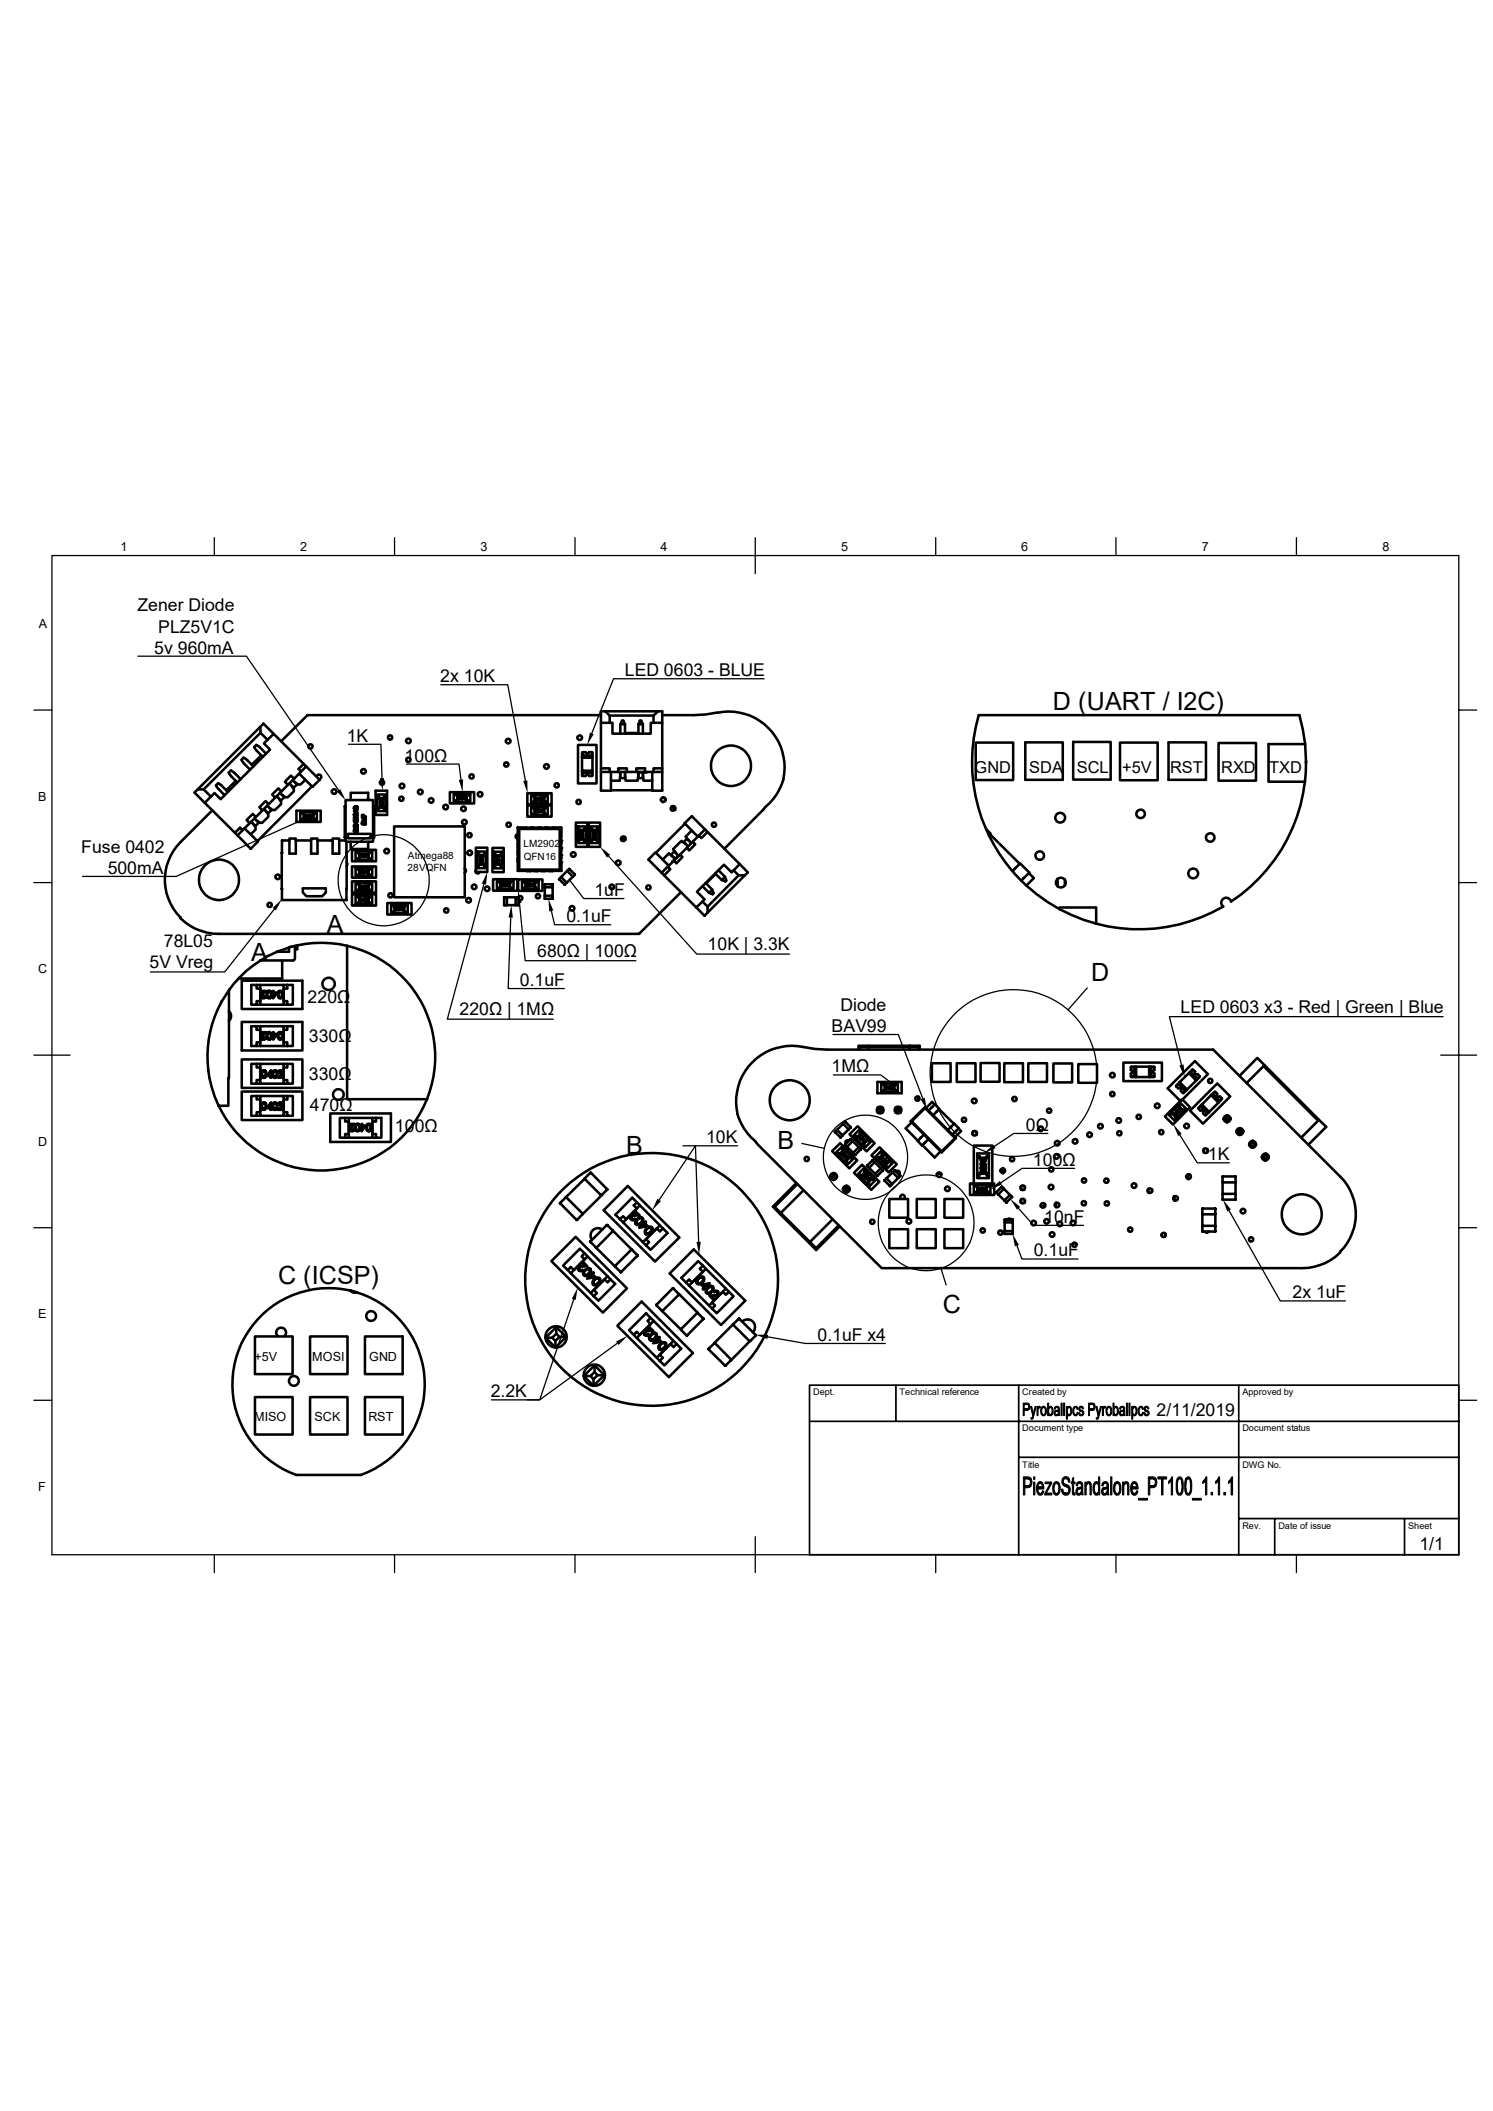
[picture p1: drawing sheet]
<svg xmlns="http://www.w3.org/2000/svg" width="297mm" height="420mm" viewBox="0 0 297 420" stroke-linecap="round" stroke-linejoin="round" font-family="sans-serif">
<defs><g id="words">
<g font-size="5">
<text x="209.5" y="141.2">D (UART / I2C)</text>
<text x="65" y="185.5">A</text>
<text x="50" y="191.2">A</text>
<text x="217.1" y="195.2">D</text>
<text x="124.5" y="229.7">B</text>
<text x="154.6" y="228.6">B</text>
<text x="55.3" y="255.5">C (ICSP)</text>
<text x="187.6" y="261.2">C</text>
</g>
<g font-size="3.5">
<text x="27.3" y="121.6">Zener Diode</text>
<text x="31.5" y="125.9">PLZ5V1C</text>
<text x="30.7" y="130">5v 960mA</text>
<text x="87.6" y="135.8">2x 10K</text>
<text x="124.3" y="134.5">LED 0603 - BLUE</text>
<text x="69" y="147.6">1K</text>
<text x="80.5" y="151.5">100Ω</text>
<text x="16.2" y="169.7">Fuse 0402</text>
<text x="21.4" y="173.9">500mA</text>
<text x="118.2" y="178.3">1uF</text>
<text x="112.7" y="183.5">0.1uF</text>
<text x="32.6" y="188.5">78L05</text>
<text x="106.9" y="190.4">680Ω | 100Ω</text>
<text x="140.8" y="189.1">10K | 3.3K</text>
<text x="29.8" y="192.6">5V Vreg</text>
<text x="103.4" y="196.2">0.1uF</text>
<text x="61.2" y="199.6">220Ω</text>
<text x="91.4" y="202">220Ω | 1MΩ</text>
<text x="167.2" y="201.1">Diode</text>
<text x="234.9" y="201.5">LED 0603 x3 - Red | Green | Blue</text>
<text x="61.4" y="207.4">330Ω</text>
<text x="165.4" y="205.3">BAV99</text>
<text x="61.4" y="214.9">330Ω</text>
<text x="165.4" y="213.4">1MΩ</text>
<text x="61.6" y="221.1">470Ω</text>
<text x="78.6" y="225.2">100Ω</text>
<text x="140.5" y="227.5">10K</text>
<text x="204" y="225">0Ω</text>
<text x="205.5" y="231.9">100Ω</text>
<text x="240.3" y="230.8">1K</text>
<text x="207.7" y="243.3">10nF</text>
<text x="205.7" y="250">0.1uF</text>
<text x="257.1" y="258.3">2x 1uF</text>
<text x="162.6" y="266.8">0.1uF x4</text>
<text x="97.6" y="278">2.2K</text>
<text x="230.1" y="281.7">2/11/2019</text>
<text x="282.4" y="308.4">1/1</text>
</g>
<g font-size="3.3">
<text x="193.9" y="153.8">GND</text>
<text x="204.8" y="153.8">SDA</text>
<text x="214.2" y="153.8">SCL</text>
<text x="223.3" y="153.8">+5V</text>
<text x="232.8" y="153.8">RST</text>
<text x="242.9" y="153.8">RXD</text>
<text x="252.5" y="153.8">TXD</text>
</g>
<g font-size="2.5">
<text x="24" y="109.6">1</text>
<text x="59.7" y="109.6">2</text>
<text x="95.6" y="109.6">3</text>
<text x="131.4" y="109.6">4</text>
<text x="167.3" y="109.6">5</text>
<text x="203.2" y="109.6">6</text>
<text x="239.1" y="109.6">7</text>
<text x="275" y="109.6">8</text>
<text x="7.7" y="125">A</text>
<text x="7.6" y="159.3">B</text>
<text x="7.6" y="193.7">C</text>
<text x="7.6" y="228">D</text>
<text x="7.6" y="262.3">E</text>
<text x="50.6" y="270.8">+5V</text>
<text x="62.1" y="270.8">MOSI</text>
<text x="73.5" y="270.8">GND</text>
<text x="50.5" y="282.7">MISO</text>
<text x="62.6" y="282.7">SCK</text>
<text x="73.3" y="282.7">RST</text>
<text x="7.6" y="296.6">F</text>
</g>
<g font-size="2">
<text x="81.1" y="173.2">28VQFN</text>
<text x="81.2" y="170.8">Atmega88</text>
<text x="104.1" y="168.6">LM2902</text>
<text x="104.2" y="171">QFN16</text>
</g>
<g font-size="1.8">
<text x="161.8" y="277.6">Dept.</text>
<text x="178.9" y="277.6">Technical reference</text>
<text x="203.4" y="277.6">Created by</text>
<text x="247.1" y="277.6">Approved by</text>
<text x="203.4" y="284.8">Document type</text>
<text x="247.1" y="284.8">Document status</text>
<text x="203.4" y="292">Title</text>
<text x="247.1" y="292">DWG No.</text>
<text x="247.1" y="304.2">Rev.</text>
<text x="254.3" y="304.2">Date of issue</text>
<text x="280.1" y="304.2">Sheet</text>
</g>
</g></defs>
<g fill="none" stroke="#000" stroke-width=".51">
<path d="M40.7 159.7l2-1.9 1.2 1.2 9.8-9.9-1.2-1.2 1.9-1.9 6 6-1 1 .5 .5-1.4 1.4-.6-.6-1.2 1.2 .6 .7-1.3 1.3-.6-.7-1.3 1.3 .6 .6-1.3 1.3-.6-.6-1.2 1.2 .6 .6-1.3 1.4-.6-.7-1.2 1.3 .6 .6-1.4 1.4-.5-.5-1.1 1M42 158.5l-1.5-1.4h-1.2l-.6 .6 8.5 8.5M45.3 157.6l-1.4-1.4-.5-.4-.4 .5 .1 .2 1.6 1.7M46.9 155.4l-1.9 1.8M47.9 155l-1.4-1.4-.6-.3-.4 .4 .1 .3 1.6 1.7M50.4 152.5l-1.4-1.4-.6-.4-.4 .5 .2 .3 1.5 1.6M51.8 145.8l-11.3 11.3M51.8 144.6l-12.5 12.5M52 150.3l-1.9 1.8M52.9 149.9l-1.3-1.4-.6-.3-.4 .4v.2l1.7 1.8M54.4 146l-2-2-.6 .6v1.2l1.4 1.4M55.3 158.7l.6 .9v.4l-1.2 1.2h-.4l-.8-.6"/>
<path d="M55.7 157.7l.9 .9-.7 .7-.9-.9M56 157.5l-1.3 1.2M57.9 156.2l.6 .8v.4l-1.3 1.2h-.4l-.8-.5M58.2 155.2l.9 .9-.7 .6-.8-.8M58.5 154.9l-1.2 1.3M60.4 152l.5 .5-1 1M60.7 155.2l-.9 .9h-.4l-.9-.6M60.9 152.5l2.7 2.7-1.5 1.3-2.6-2.6M62.1 156.5l-10.9 10.8M63 154.5a.46 .46 0 0 1 .5-.4 .46 .46 0 0 1 .4 .4 .46 .46 0 0 1-.4 .5M68.7 159.3v8M68.8 159.3l.1-.1h5.2l.1 .1v8l-.1 .2h-5.2"/>
<path d="M69.8 159.2v-1.5h3.4v1.5M74.7 157.3h2.3v4.8h-2.3zM75.1 158.8h1.6v1.9h-1.6zM75.1 158.1h1.6v.4h-.3v.3h-1v-.3h-.3zM75.1 158.5v.3M75.6 159.8l.4-.1 .2 .2h-.2v.2zM75.6 159.4l.4-.1 .2 .3-.5 .1zM75.6 158.9h.3l.2 .2 .1-.3v.5l-.4-.4-.2 .1 .2 .2h-.2zM75.6 159.4l.4-.1 .1 .3h-.4zM75.7 159.9h.3v.1zM75.8 159.2h.1M76.7 158.5v.3"/>
<path d="M89.5 157.6h4.8v2.3h-4.8zM90.3 157.9h.4v.3h.3v1h-.3v.3h-.4zM90.7 157.9h.3M90.7 159.5h.3M91 157.9h1.8v1.6h-1.8zM91.1 158.4h.3l-.2 .2 .1-.1zM91.1 158.8l.1-.1-.1 .2h.3l-.3 .1zM91.5 158.5h.4l-.1 .5-.3-.1zM92 158.4v.1h.3l-.3 .5zM92 158.6h.2l-.2 .3zM92.5 158.5l.2 .1-.1 .4-.2-.2zM92.5 158.4l.2 .1a.3 .3 0 0 1 .1 .3 .3 .3 0 0 1-.3 .2l-.1-.2z"/>
<path d="M92.8 157.9h.8v1.6h-.5M92.8 159.5h.3M93.1 157.9v.3h-.3v1h.3v.3M104.9 157.8h4.8v2.3h-4.8zM106.1 158.2v.3h.3v.9h-.3v.3M106.1 158.2h-.4v1.5h.7M106.1 158.2h.3M106.4 158.2h1.8v1.5h-1.8zM106.5 158.8l.3-.1v.6l-.3-.2zM106.6 158.8h.2l-.1 .4h-.1zM107.2 158.8v.2h-.2zM107.2 158.7l.1 .4-.1 .2v-.2h-.3z"/>
<path d="M107.4 158.7l.3 .1v.5l-.3-.2zM107.4 158.8h.3l-.1 .4-.2-.1zM107.8 158.8l.4-.1v.3l-.3 .2 .3 .1h-.4l.3-.4v-.1l-.2-.1v.2zM108.2 158.5h.3v-.3h.5v1.5h-.5v-.3h-.3zM108.2 159.7h.3M108.2 158.2h.3M115 148.2h3.7v7.7h-3.7zM115.8 150.7h2.1v2.6h-2.1zM115.8 153.3v.2h2.1M115.8 150.7v-.1h2.1v.1M115.8 153.5v.8h.1M115.9 154.4v-.6h1.9v.6h-.6l-.3-.3-.3 .1-.1 .2"/>
<path d="M115.9 149.7h-.1v.9M115.9 154.4h.6M116.5 149.6h-.6v.7h1.9v-.7h-.6l-.3 .4-.3-.1-.1-.3M117.8 149.7l.1 .9M117.9 153.5l-.1 .8M117.9 153.3v.2M119.5 152.9h1.8v.7M119.5 143.8h2.3v2.2h7.7v-2.2h2.2v9.1h-1.7v.7M119.5 153.6h12.2M119.5 142.3h-58.3l-5.3 5.2M120.4 141.5l.9 .9v1.4M121.3 142.4h8.7"/>
<path d="M121.5 157.2h8.3M123 153.6v-.7h1.7v.7M123.4 144.1v1.9M123.4 153.6v1.2h.9v-1.2M123.4 153.9l-.1 1.4h-1.8M123.7 143.4h.3l.3 .7h-.9zM124.3 154.1l.2 1.2h2.3l.2-1.2M124.3 144.1v1.9M124.3 145.8h2.7M126.6 153.6v-.7h1.7v.7M127 144.1v1.9M127 153.6v1.2h.9v-1.1"/>
<path d="M127 144.1l.3-.7h.3l.3 .7M127 144.1h.9M127.1 153.6l1 .1M127.9 153.9l.1 1.4h1.8M127.9 144.1v1.9M128.1 153.6h.5M130 142.4l.9-.9h.8v2.3M130 142.4v1.4M130.9 141.5h-11.4v15.8h2v-3.7M131.4 159.1l.5 .5M131.7 152.9v4.4h-1.9v-3.7M131.9 158.6l.6 .5"/>
<path d="M142.6 141.8a11.1 11.1 0 0 1 13.2 13.2M142.6 141.8l-2.3 .4-2.3 .1h-6.3M155.9 155a11.1 11.1 0 0 1-3.7 5.6l-8.1 8.3M194.1 147.7h7.4v7.5h-7.4zM204 147.7h7.4v7.5h-7.4zM213.5 147.6h7.4v7.5h-7.4zM222.8 147.7h7.5v7.5h-7.5zM232.5 147.7h7.4v7.5h-7.4zM242.4 147.8h7.5v7.5h-7.5zM259.6 155.5a33.1 33.1 0 0 1-14.7 23.9 .98 .98 0 0 0-1.5-.6 .98 .98 0 0 0-.1 1.5M259.6 148a37 37 0 0 1 0 7.5M259.6 148h-7.3v7.5h7.3"/>
<path d="M259.6 148l-.4-2.9-.7-2.8h-63.8a33.1 33.1 0 0 0 1.5 22.7l.9 .9-.4 .3a33.6 33.6 0 0 0 4.7 7.1M42.2 161.2l-6.3 6.4a10.7 10.7 0 0 0-2.2 11.6 10.7 10.7 0 0 0 9.9 6.6h83.5l8.4-8.3M48.3 165.2l-1.1 1M48.6 164.8l2.7 2.6-1.4 1.5-2.7-2.7M50.2 163.8l.6 .8v.5l-.9 .9M50.6 162.8l.9 .9-.7 .6-.8-.8M50.9 162.6l-1.2 1.2M52.8 161.2l.6 .9v.4l-1.2 1.2h-.5l-.8-.5M53.1 160.3l.9 .9-.7 .6-.8-.8M53.4 160l-1.2 1.2M56 169.7l.1 7.2M56.1 176.9h.1"/>
<path d="M56.1 176.8v2.3h12.8l.1-2.3M56.1 169.7h.1M57.6 166.8h1.2v3h-1.2zM57.6 167.2h-1.5v2.5M58.8 167.2h3.1M59 161.3h4.8v2.2h-4.8zM60.2 161.6v.3h.3v1h-.3v.3M60.2 161.6h-.5v1.6h.8M60.2 161.6h.3M60.2 176.7h4.6v.9l-.7 .7h-3.1l-.8-.7zM60.5 161.6h1.8v1.6h-1.8zM60.6 162.2a.22 .22 0 0 1 .2 0 .22 .22 0 0 1 .1 .2v.3h-.3z"/>
<path d="M60.6 162.2l.3 .1-.1 .4-.2-.1zM61.3 162.3v.2h-.2zM61.3 162.1l.1 .5-.1 .1v-.1h-.3zM61.5 162.2l.2-.1 .1 .2-.1 .4-.3-.1zM61.5 162.2l.3 .1-.1 .4-.2-.1zM61.9 166.8h1.3v3h-1.3zM61.9 162.2h.3l-.2 .4 .2 .1h-.4l.4-.3-.1-.2-.2 .1zM62.3 161.9h.3v-.3h.4v1.6h-.4v-.3h-.3zM62.3 163.2h.3M62.3 161.6h.3M63.2 167.2h3M66.2 166.8h1.3v3h-1.3z"/>
<path d="M66.2 167.1l-.4 .2M67.5 167.2h1.2M68.7 160.4h-.1v6.2h.1M68.8 167.3l.1 .2M68.9 169.7h.1M68.9 167.5v2.3M69 171.5l.1 .3-.1 .5M69 169.7v7.1M69.2 165.9h4.5v.9h-4.5zM69.8 167.5v1.4h3.4v-1.4M70 177.9h4.8v2.3h-4.8zM70 175.3h4.8v2.3h-4.8z"/>
<path d="M70 172.4h4.8v2.2h-4.8zM70 169.1h4.8v2.3h-4.8zM70.4 161.4l.8-.4-.3 .2v.3l.3 .3zM70.4 162.6l.8 .1h-.7v.1zM70.4 164.2l.2-.2h.4l.2 .2-.1 .4-.2 .2-.4-.1zM70.4 160.6l.6-.2 .2 .5h-.8zM70.4 163.1l.2-.1 .3 .2-.4-.1v.3h.2l-.1 .1-.2-.1zM70.5 160.6h.2v.2h-.2zM70.5 161.9l.2-.1 .5 .4-.4-.2v.2a.23 .23 0 0 1-.3 .1 .23 .23 0 0 1 0-.4zM70.5 165l.1-.1a.36 .36 0 0 1 .4 0 .36 .36 0 0 1 .2 .4v.2h-.8zM70.5 161.4l.3-.2v.3zM70.5 165.1l.2-.2 .3 .1 .1 .4h-.6z"/>
<path d="M70.7 172.7h.5v.3h.3v1h-.3v.3h-.5zM70.7 169.4h.5v.3h.3v1h-.3v.3h-.5zM70.8 163.6l.1 .3zM70.8 160.6h.3v.2h-.3zM70.9 163.2l.2 .2 .1-.4v.5zM71.2 178.3v.3h.3v.9h-.3v.3M71.2 178.3h-.5v1.5h.8M71.2 175.7v.3h.3v1h-.3v.3M71.2 175.7h-.5v1.6h.8M71.2 169.4h2.8v1.6h-.4M71.2 172.7h.3M71.2 178.3h.3"/>
<path d="M71.2 175.7h.3M71.2 174.3h.3M71.2 171h.3M71.5 178.3h1.8v1.5h-1.8zM71.5 175.7h1.8v1.6h-1.8zM71.5 172.7h1.8v1.6h-1.8zM71.5 169.4v1.6h1.8M71.5 173.2h.4l-.3 .4 .1 .1 .2-.1-.1 .2-.3-.1 .3-.4zM71.5 169.9h.4l-.3 .4 .1 .1 .2-.1-.1 .2-.3-.1 .3-.4zM71.6 176.3h.3l-.1 .5-.2-.1zM71.6 178.9h.3v.4l-.3-.1zM71.6 176.4h.3l-.1 .4-.2-.1z"/>
<path d="M72 162.1l.1 .3h.2l.1-.3v.3l.4 .1h-.8zM72 162.8l.8-.2-.6 .2 .6 .3-.6 .3 .6 .1-.8-.1 .6-.3zM72 173.3h.3v.5l-.3-.1zM72 163.7h.2l-.1 .2 .1 .1 .4-.4 .2 .4-.2 .1 .1-.4h-.2l-.2 .3h-.2zM72.1 173.3h.2l-.1 .4h-.1zM72.1 169.9l.2 .1v.5l-.3-.1zM72.1 170h.2l-.1 .4-.1-.1zM72.3 178.9v.3h-.2zM72.3 176.4v.2h-.2zM72.3 178.8l.1 .4-.1 .2v-.2h-.3zM72.3 176.2l.1 .5-.1 .1v-.1h-.3zM72.5 178.9l.2-.1a.26 .26 0 0 1 .2 .3 .26 .26 0 0 1-.3 .2 .26 .26 0 0 1-.2-.3z"/>
<path d="M72.5 176.3a.28 .28 0 0 1 .3 .2 .28 .28 0 0 1-.1 .3l-.2-.1zM72.5 173.2l.3 .1-.3 .5zM72.5 169.9l.3 .2-.3 .4zM72.6 178.9h.2l-.1 .4-.2-.1zM72.6 173.4h.1l-.1 .3zM72.6 170.1h.1l-.1 .2zM72.6 176.3l.2 .1-.2 .4-.1-.1zM72.9 173.3h.3v.5l-.3-.1zM72.9 170l.3-.1v.6a.34 .34 0 0 1-.3-.5zM72.9 178.9l.3-.1 .1 .2-.3 .3 .3 .1h-.4l.3-.4-.1-.2-.1 .2zM72.9 173.3h.3l-.1 .4h-.2zM72.9 170l.3 .1-.1 .3h-.2z"/>
<path d="M72.9 176.3h.4l-.3 .4 .3 .1h-.4l.3-.4v-.1l-.3 .1zM73.3 176h.3v-.3h.4v1.6h-.4v-.3h-.3zM73.3 172.7h.7v1.6h-.4M73.3 169.4v1.6M73.3 179.8h.3M73.3 177.3h.3M73.3 178.3h.3M73.3 175.7h.3M73.3 174.3h.3M73.3 171h.3M73.6 178.3h.4v1.5h-.4v-.3h-.3v-.9h.3zM73.6 172.7v.3h-.3v1h.3v.3"/>
<path d="M73.6 169.4v.3h-.3v1h.3v.3M74.2 160.4h.2v6.2h-.2M75.1 161h.3v-.3h1v.3h.3M75.1 160.7v.3M75.6 160.3l.5-.1 .1 .2-.5 .2zM75.6 160.3l.4-.1 .1 .2-.3 .1zM76.7 160.7v.7h-1.6v-.4M77 179.7h4.9v2.2h-4.9zM78.4 164.4h14.1v14.1h-14.1zM92.4 172.8l.3 .4-.3 .5M94.7 168.7h2.2v4.8h-2.2zM94.7 173a.46 .46 0 0 0 .1 .7 .46 .46 0 0 0 .7-.2"/>
<path d="M95 172v-1.9h1.6v1.9M95 169.8h.3v.3h1v-.3h.3M95 172h1.6M95 172v.3M95.3 172h1v.3h.3v.4h-1.6v-.4h.3zM95.5 171.2l.4-.1 .2 .3-.5 .1zM95.5 170.3l.4-.1 .2 .1v.2l-.5 .1zM95.5 171.6l.3 .3 .2-.1v-.2l.1 .3-.2 .1-.4-.3v.3zM95.5 171.2h.4l.1 .2-.4 .1zM95.5 170.3h.5v.2l-.4 .1zM95.6 170.7l.5 .3h-.6l.1-.1zM95.7 170.8l.2 .1h-.2z"/>
<path d="M96.6 169.8v-.4h-1.6v.7M96.6 169.8v.3M96.6 172v.3M98 168.7h2.2v4.8h-2.2zM98.1 174.9h4.8v2.3h-4.8zM98.3 170.2h1.6v1.8h-1.6M98.3 169.9h.3v.3h1v-.3h.3M98.6 172h1v.3h.3v.5h-1.6v-.5h.3zM98.8 171.2h.4l.2 .2-.5 .1zM98.8 170.3h.4l.2 .2-.6 .1zM98.8 171.6l.5 .3-.2-.2a.16 .16 0 0 1 .2 .2 .16 .16 0 0 1-.3 0l-.2-.2v.3zM98.8 170.4v-.1a.21 .21 0 0 1 .3 0 .21 .21 0 0 1 .1 .3h-.3z"/>
<path d="M98.8 171.2h.4l.1 .3h-.4zM98.8 175.3h.5v.3h.3v1h-.3v.2h-.5zM98.9 170.7l.5 .3-.5 .1-.1-.1h.1zM98.9 170.8l.3 .2h-.3zM99.3 176.8h.3M99.3 175.3h.3M99.6 175.3h1.8v1.5M99.6 175.3v1.5h1.8M99.6 175.7h.4l-.3 .4v.2l.3-.2-.1 .2h-.2l-.1-.2 .3-.3zM99.9 170.2v-.7h-1.6v2.8M99.9 172v.3M100.1 175.8a.26 .26 0 0 1 .3 .2 .26 .26 0 0 1-.3 .3z"/>
<path d="M100.1 175.9l.1-.1a.2 .2 0 0 1 .2 .2 .2 .2 0 0 1-.3 .2zM100.3 178.5h.5M100.3 178.5v1.6M100.3 178.5v.1M100.6 175.7v.2h.3l-.3 .4zM100.6 175.9h.2l-.2 .3zM100.8 178.5h1.8v1.6h-1.8zM101 175.9h.3l-.1 .4-.2-.1zM101 175.8a.26 .26 0 0 1 .4 .3 .26 .26 0 0 1-.4 .2zM101.4 175.3h.8v1.5h-.5M101.4 176.8h.3M101.7 175.3v.3h-.3v1h.3v.2"/>
<path d="M102.6 178.5h.6M102.6 178.5v.1M103 164.7h8.6l-.3 .2h-8zM103 165.9a.47 .47 0 0 0-.4 .5 .47 .47 0 0 0 .4 .5M103 170.7v.9M103 166.4v.9M103 167.8v.9M103 169.2v.9M103.1 175h4.8v2.3h-4.8zM103.1 178.5v.1M103.1 178.5a.43 .43 0 0 1 .7-.2 .43 .43 0 0 1 0 .7 .43 .43 0 0 1-.6-.1M103.2 178.5v1.6l-.6-.1"/>
<path d="M103.3 164.9v8.1M103.8 175.3h.5v.3h.3v1h-.3v.3h-.5zM104.3 175.3h.3M104.3 176.9h.3M104.6 175.3h1.8v1.6h-1.8zM104.6 175.8h.4l-.3 .3v.2l.3-.1-.1 .2-.3-.1v-.2l.3-.2zM104.7 173.3h.9M104.8 164.7h-1.8v8.6h8.6M104.9 160.2h4.8v2.3h-4.8zM105.1 175.9l.1-.1a.34 .34 0 0 1 .2 .5h-.3zM105.2 175.9l.1-.1 .1 .1-.1 .4-.2-.1zM105.6 175.8v.1h.3l-.3 .5z"/>
<path d="M105.6 164.7h.6M105.6 176h.2l-.2 .2zM106 175.9l.1-.1a.37 .37 0 0 1 .2 .6l-.3-.2zM106 175.9h.3l-.1 .4-.2-.1zM106.1 160.6v.2h.3v1h-.3v.3M106.1 162.1h.3M106.2 173.3h.8M106.4 160.6h1.8v1.5h-1.8zM106.4 160.6h-.7v1.5h.4M106.4 161h.4l-.3 .3v.2l.3-.1a.17 .17 0 0 1-.2 .2 .17 .17 0 0 1-.2-.2 .17 .17 0 0 1 .2-.2l.1-.1zM106.4 175.3h.7v1.6h-.7M106.7 175.3v.3h-.3v1h.3v.3"/>
<path d="M106.9 161.1l.3-.1 .1 .5-.2 .1-.2-.1zM106.9 161.2l.3-.1-.1 .4h-.1zM107 164.7h.7M107.4 161v.2h.3l-.3 .4zM107.4 161.2h.2l-.2 .3zM107.6 173.3h.9M107.8 161.1l.3-.1 .1 .2a.25 .25 0 0 1 0 .3 .25 .25 0 0 1-.4 .1 .25 .25 0 0 1 0-.4zM107.8 161.2h.3l-.1 .3h-.2zM108.2 160.6h.8v1.5h-.5M108.2 162.1h.3M108.4 176.5h1.5v1.7h-1.5zM108.4 176.5v-.6h1.5v.6"/>
<path d="M108.4 178.2v.6h1.5v-.6M108.4 178.8h.1M108.4 176.5h.1M108.4 178.2v.1M108.4 175.9v.1M108.5 164.7h.6M108.5 160.6v.2h-.3v1h.3v.3M109.1 173.3h.8M109.9 164.7h1.7M109.9 178.2v.1M109.9 175.9v.1M109.9 178.8h.1"/>
<path d="M109.9 176.5h.1M111.3 175l1 1M111.3 174.9v.1M111.3 173h-8l-.3 .3M111.6 174.5h.1M111.6 164.7v8.6l-.3-.3v-8.1M111.6 170.1l.1 .6M111.6 168.7l.1 .5M111.6 167.3l.1 .5M111.6 164.7l.1 1.7M111.6 173.3h.1M111.6 171.6v1.7"/>
<path d="M111.6 174.5l-.3 .5M112.3 176h.1M112.4 176h.1M112.7 175.6l-.3 .4M112.7 175.6v.1M112.8 173.3l1.2 1.1-1.3 1.2-1.1-1.1zM112.8 173.3h.1M112.9 173.3l.3-.4 1.1 1-.3 .5M112.9 173.2v.1M113.2 172.9h.1M113.9 174.4h.1M114.6 163.7h2.2v4.8h-2.2z"/>
<path d="M114.9 165.1h1.6v1.9h-1.6zM114.9 164.8h.3v.3h1v-.3h.3M114.9 167v.3M115.2 167h1v.3h.3v.4h-1.6v-.4h.3zM115.4 166.2l.5-.1 .1 .2-.4 .2-.2-.1zM115.4 166.5l.3 .4 .2-.1-.1-.2h.1l.1 .3h-.3l-.3-.2v.2zM115.4 165.3l.5-.1 .1 .2a.33 .33 0 0 1-.3 .2 .33 .33 0 0 1-.3-.2zM115.4 166.2h.4l.1 .2h-.4zM115.4 165.4l.4-.1 .1 .2-.3 .1zM115.5 165.7l.5 .3h-.6l.1-.1zM115.6 165.8l.2 .1h-.2zM115.8 166.6h.1"/>
<path d="M116.5 164.8v-.4h-1.6v.7M116.5 164.8v.3M116.5 167v.3M117.1 163.7h2.3v4.8h-2.3zM117.5 165.1h1.5v1.9h-1.5zM117.5 164.4h1.5v.4h-.3v.3h-.9v-.3h-.3zM117.5 167.3h.3v-.3h.9v.3h.3M117.5 164.8v.3M117.5 167v.3M118 166.2l.4-.1 .2 .1h-.2v.3zM118 165.3l.2-.1 .3 .2 .1-.2v.4l-.5-.3v.3zM118 165.7h.5a.29 .29 0 0 1-.2 .4 .29 .29 0 0 1-.3-.4z"/>
<path d="M118 166.6l.5-.1a.27 .27 0 0 1-.2 .4 .27 .27 0 0 1-.3-.3zM118.1 166.6h.3l.1 .2h-.4zM118.1 166.2h.3v.2zM118.1 165.7h.4a.21 .21 0 0 1-.2 .3 .21 .21 0 0 1-.2-.3zM119 167v.7h-1.5v-.4M119 164.8v.3M124.3 166.5l-.7 .7M132.8 172.4l-1.2 1.3M133.1 172.3l-2.7-2.7-1.4 1.4 3.1 3.2M133.5 161.1l.1 .1M133.6 160.4l.7 .7M134.1 171.2l-1.3 1.2"/>
<path d="M134.1 170.7l-1-.9-1.3 1.2M134.2 171.1l-.3 .3M134.9 170.3l-.7 .7M135 170.3l-.9-.9-.6 .7 .8 .8M135.3 170l.5 .5-1.2 1.2-.5-.5M136.3 163.9l-5.8 5.8M136.5 168l-.9-.7-1.7 1.7 .7 .9M137.5 167.7l-.8-.8-.7 .6 .9 .9M137.6 165.2l-1.2 1.3 .9 1M137.8 167.5l.5 .5-1.2 1.2-.5-.5M138.8 166.5l-2.6-2.7 1.4-1.4 9.6 9.5M139.7 176.3l1.4 1.3"/>
<path d="M139.7 179.4l1.1 1M140.3 165l-6.2 6.2M140.4 175.7l1.3 1.3M140.8 165.5l-1.3 1.3-.5-.6M141.1 177.6l.6-.6 .2 .7-.1 .2zM142.2 173.8l1.4 1.3M142.4 173.9l-1.9 1.9M142.9 173.1l1.3 1.4M143.6 175.1l.6-.6 .3 .7-.2 .2zM145.9 173.1l1 1.1h1.3M146.9 174.2l-6.1 6.2M147.2 171.9l-1.7 1.7-1.5-1.6-5.4 5.4 1.6 1.5-1.7 1.7-6.4-6.4 1.2-1.3-.5-.5"/>
<path d="M147.2 171.9l1.6 1.7-8 8M196.2 165l.6 1.2M196.9 166l6 5.9M201.4 173.3l1.5-1.5 1.9 1.8-1.6 1.6M201.4 173.3l1.8 1.9M203.2 175.2l1 1M204.2 176.2l2 1.7 2.2 1.6 2.4 1.4M204.7 173.7l1 1-1.5 1.5M210.4 174.8v1.6M211.8 175v1.2M44 199.4a22.4 22.4 0 0 0-2.6 13.6M44 199.3l-.1 .1"/>
<path d="M45.6 196.9v17.6M48.1 195.1h12.1v5.6h-12.1zM50 196h1.1v.7h.7v2.5h-.7v.7h-1.1zM51.1 196h.7M51.1 199.9h.7M51.8 196h4.6v3.9h-4.6zM51.9 197.1h1l-.5 .6a.41 .41 0 0 0-.3 .4 .41 .41 0 0 0 .1 .4h.3l.4-.3-.3 .4h-.3a.52 .52 0 0 1-.3-.4 .52 .52 0 0 1 .2-.5l.4-.4h-.7zM52.7 190.5a22.7 22.7 0 0 0-8.6 8.8M53.2 197.2l.4-.1 .4 .3v.8l-.3 .4-.4-.1-.2-.2-.1-.7zM53.3 197.4a.34 .34 0 0 1 .4-.1 .34 .34 0 0 1 .2 .3l-.1 .7-.4 .2-.2-.4zM53.4 190.2l-.7 .3M54.3 197.1h.1v.4h.7l-.7 1.1-.1-1h-.2v-.1h.2z"/>
<path d="M54.4 197.6h.5l-.5 .6zM55.1 189.4l-1.7 .8M55.4 197.3l.4-.2 .4 .4a1.06 1.06 0 0 1-.2 1.1h-.4l-.3-.2-.1-.7zM55.5 197.4l.4-.1 .1 .1 .1 .8-.2 .3h-.3l-.2-.3zM56.1 191.1v3.6h-8.6v-.1M56.4 196h1.9v3.9h-1.2M56.4 199.9h.7M57.1 196v.7h-.7v2.5h.7v.7M57.5 188.5v.9h-2.4M57.7 188.4l-2.6 1M58 188.3l-.3 .1M58.6 190.8l-.1 .2-.2 .1h-6.6"/>
<path d="M58.7 188.2v2.6M59.1 188.1v.8h-.4M59.1 188.1a22.6 22.6 0 0 1 9.9 .1M59.1 188.1l-1 .2M69 188.2a22.7 22.7 0 0 1 16 30.5M69 188.2v30.5h16M77.8 180h.4v.3h.3v1h-.3v.3h-.4zM78.2 180h.3M78.2 181.6h.3M78.5 180h1.9v1.6h-1.9zM78.6 180.5h.4l-.3 .3v.2l.3-.1-.1 .2-.3-.2 .3-.3zM79 180.6l.2-.1 .2 .1-.1 .5-.2-.1z"/>
<path d="M79.5 180.5l.1 .1h.2l-.3 .5zM79.6 180.7h.2l-.2 .2zM79.9 180.6l.2-.1a.28 .28 0 0 1 .2 .3 .28 .28 0 0 1-.3 .2zM80 180.6a.2 .2 0 0 1 .3 .2 .2 .2 0 0 1-.3 .1zM80.4 180h.7v1.6h-.4M80.4 181.6h.3M80.7 180v.3h-.3v1h.3v.3M100.3 180.1h.5M100.3 180v.1M100.8 180v.1M103.1 180v.1M140.8 180.4v1.2l-.6 .6-1.7-1.6"/>
<path d="M210.8 180.9l4.8 2.1 2.5 .8M210.8 180.9v-.3h7.3v3.2M243.3 180.4a33.4 33.4 0 0 1-25.2 3.4M41.4 213v.1M41.4 213a22.7 22.7 0 0 0 19.6 19.7 22.7 22.7 0 0 0 24-14M45.4 214.4v5.6h-2M45.4 214.6h.1M45.5 201.2a1.25 1.25 0 0 1 0 1.9M45.5 214.5h.1M48.1 217.2h12.1v5.6h-12.1zM48.1 210.8h12.1v5.7h-12.1zM48.1 203.3h12.1v5.7h-12.1z"/>
<path d="M50 204.2h1.1v.7h.7v2.5h-.7v.7h-1.1zM51.1 218.1v.6h.7v2.6h-.7v.7M51.1 218.1h-1.1v3.9h1.8M51.1 211.7v.7h.7v2.5h-.7v.7M51.1 211.7h-1.1v3.9h1.8M51.1 204.2h.7M51.1 218.1h.7M51.1 211.7h.7M51.1 208.1h.7M51.8 218.1h4.6v3.9h-4.6zM51.8 211.7h4.6v3.9h-4.6zM51.8 204.2h4.6v3.9h-4.6z"/>
<path d="M51.9 205.4h1l-.8 .8a.33 .33 0 0 0 .3 .5 .33 .33 0 0 0 .3-.3h.2l-.1 .2-.2 .2h-.4a.5 .5 0 0 1-.2-.4 .5 .5 0 0 1 .2-.5l.4-.4h-.7zM52.1 219.5l.5-.2 .4 .5-.1 .8-.2 .2h-.4a1.13 1.13 0 0 1-.2-1.3zM52.1 213.1l.2-.1a.47 .47 0 0 1 .6 .4l.1 .6a.49 .49 0 0 1-.6 .5 .49 .49 0 0 1-.4-.6zM52.2 219.6l.3-.1 .2 .1 .1 .7a.33 .33 0 0 1-.2 .4 .33 .33 0 0 1-.4-.2zM52.2 213.2l.3-.1 .3 .2v.7a.37 .37 0 0 1-.2 .3 .37 .37 0 0 1-.4-.1zM53.2 205.4l.4-.1a.83 .83 0 0 1 .4 1.2l-.3 .3-.5-.1-.2-.9zM53.3 205.6a.35 .35 0 0 1 .4-.1 .35 .35 0 0 1 .2 .3v.5a.36 .36 0 0 1-.4 .4 .36 .36 0 0 1-.3-.4zM53.8 219.7v.6h-.5zM53.8 213.3v.6h-.5zM53.9 219.3v1h.2v.2h-.2v.3h-.1v-.3h-.7zM53.9 212.9v1h.2v.2h-.2v.3h-.1v-.3h-.7zM54.3 213.2l.3-.3 .3 .1 .3 .4v.6a.47 .47 0 0 1-.5 .5 .47 .47 0 0 1-.5-.4z"/>
<path d="M54.3 205.4h.1v.3h.7l-.7 1.1-.1-.9h-.2v-.2h.2zM54.4 219.4l.4-.1 .4 .5v.6l-.3 .4h-.4l-.3-.3v-.8zM54.4 219.6a.34 .34 0 0 1 .4-.1 .34 .34 0 0 1 .2 .3v.6a.34 .34 0 0 1-.3 .3 .34 .34 0 0 1-.3-.4zM54.4 205.9h.5l-.5 .6zM54.4 213.2a.36 .36 0 0 1 .6 .2v.7l-.4 .2-.2-.3zM55.4 205.5l.4-.2 .4 .4a1.06 1.06 0 0 1-.2 1.1h-.4l-.3-.2-.1-.7zM55.4 219.5l.3-.2 .5 .2 .1 .4-.7 .7h.7v.2h-1l.8-.9-.1-.4h-.3l-.2 .3h-.1zM55.4 213.1l.3-.2 .4 .1 .2 .5-.7 .7h.7v.2h-1l.8-.9-.1-.4h-.3l-.2 .3h-.1zM55.5 205.6l.4-.1 .1 .1 .1 .8a.32 .32 0 0 1-.2 .3 .32 .32 0 0 1-.4-.1l-.1-.4zM56.4 212.4h.7v-.7h1.2v3.9h-1.2v-.7h-.7zM56.4 218.7h.7v-.6h1.2v3.9h-1.2v-.7h-.7zM56.4 204.2h1.9v3.9h-1.2"/>
<path d="M56.4 215.6h.7M56.4 218.1h.7M56.4 211.7h.7M56.4 208.1h.7M57.1 204.2v.7h-.7v2.5h.7v.7M171.1 208.8v-.5h11.6v.5M172.8 208.1h-2v.7M172.8 208.1v.7M172.8 208.1h10.2v.7M174.5 215.3h4.9v2.2h-4.9zM175.7 215.6v.3h.3v1h-.3v.3M175.7 215.6h-.4v1.6h.7"/>
<path d="M175.7 215.6h.3M176 215.6h1.9v1.6h-1.9zM176.1 216.2l.3-.1 .1 .1-.1 .5-.3-.1zM176.8 216.3v.2h-.1zM176.9 216.1l.1 .5-.2 .1v-.1h-.2zM177.1 216.2l.2 .1-.1 .4-.2-.2zM177.1 216.1l.3 .1-.1 .5-.3-.1zM177.5 216.2h.3v.2l-.3 .3h.3h-.4l.4-.3-.1-.2-.2 .1zM177.9 215.9h.3v-.3h.4v1.6h-.4v-.3h-.3zM177.9 217.2h.3M177.9 215.6h.3M181 208.1v.7"/>
<path d="M182.7 218.2v.7M185.4 211.5h3.7v3.8h-3.7zM185.9 219.8l-.5-.6-1.2 1.3M190.3 211.5h3.8v3.8h-3.8zM195.1 211.5h3.7v3.7h-3.7zM199.8 211.5h3.7v3.8h-3.7zM204.6 211.5h3.7v3.8h-3.7zM209.5 211.6h3.8v3.8h-3.8zM214.5 211.7h3.7v3.7h-3.7zM223.5 211.4h7.6v3.7h-7.6zM225 213.6l.3-.3-.1-.3-.2-.1v-.6h.6v1.9h-.6v-.6M225 214.2v.1h.9"/>
<path d="M225.9 212.2l-.9 .1M226 212.2h2.6v2.1h-2.6zM226 212.2h-.1v2.1h.1M228.6 212.2h.1M228.7 212.2v2.1h-.1M228.7 212.2l.9 .1M229.6 214.2v.1h-.9M229.7 213.6l-.4-.3 .1-.3 .3-.1v-.6h-.7v1.9h.7v-.6M234 216.2l.4-.5 1.4 1.3-.5 .5-.4-.5v-.4l-.3-.1h-.2zM234.6 219.8l.3-.3 1.1 1.1-.3 .3-.2-.2-.3 .2-.6-.7 .1-.2zM234.6 215.4l-.7 .6 .1 .1M234.6 219.8l-.2 .2"/>
<path d="M234.7 215.3l1.8-1.8 1.5 1.5-1.9 1.8zM234.7 215.3l-.1 .1 1.5 1.5M236.1 216.9l-.7 .6-.1-.1M236.1 216.8v.1M236.5 213.5l.1-.1 1.5 1.4-.1 .2M236.9 213.3l.4-.5 .4 .4v.4l.3 .2 .3-.1 .3 .4-.4 .5zM237.3 212.9l-.1-.1-.6 .6M237.7 211.1l2.6 2.6-5.4 5.4-2.6-2.6zM238.6 214.2h.1l-.6 .6M239 219.8l-.6 .6 .1 .1M239.1 219.8h-.1l1.5 1.5M240.9 217.9l1.5 1.5-1.9 1.8-1.4-1.4z"/>
<path d="M240.9 217.9l.1-.1 1.5 1.5-.1 .1M241.3 217.7l.5-.5 .3 .4v.2l.1 .4 .5-.1 .4 .4-.5 .5zM241.7 217.3l-.7 .5M242.1 215.6l2.6 2.5-5.4 5.5-2.6-2.6zM243 218.6l-.5 .7M246.6 214l3.5-3.5 13.7 13.7-3.5 3.6M251.3 212.1l10.9 10.9M251.5 211.9l-3.5 3.6M56.4 222h.7M65.7 221.5h12.1v5.7h-12.1zM67.6 222.4h1.1v.7h.7v2.5h-.7v.8h-1.1zM68.7 222.4h.7"/>
<path d="M68.7 226.4h.7M69.4 222.4h4.7v4h-4.7zM69.6 223.6h.9l-.7 .8-.1 .3 .4 .2 .4-.3a.48 .48 0 0 1-.4 .4 .48 .48 0 0 1-.5-.2v-.3l.6-.8h-.6zM70.8 223.8l.2-.2a.74 .74 0 0 1 .6 1.1 .49 .49 0 0 1-.5 .3 .49 .49 0 0 1-.4-.5zM70.9 223.8l.3-.1 .3 .3v.7l-.3 .2a.64 .64 0 0 1-.3-1zM71.9 223.6h.2v.3h.6l-.7 1.2-.1-1h-.1v-.2h.1zM72.1 224.1h.4l-.4 .6zM73 223.8l.5-.2 .3 .2v.9a.47 .47 0 0 1-.5 .4 .47 .47 0 0 1-.4-.4zM73.2 223.8l.3-.1 .2 .3v.7l-.2 .2a.61 .61 0 0 1-.4-1zM74.1 222.4h1.8v4h-1.1M74.1 226.4h.7M74.8 222.4v.7h-.7v2.5h.7v.8"/>
<path d="M111.5 239.5l3.3 3.2 1.1-1.1M111.5 239.3v.2M112.5 238.3h.2M112.6 238.2l3.7-3.7 3.3 3.4-3.6 3.6zM112.6 238.2l-1.2 1.2 .1 .1M116.3 234.5l1.2-1.2 3.2 3.3M116.4 234.4v.2M117.4 233.4h.2M119.5 237.7h.2M119.7 237.7l-.1 .2M120.7 236.6h.1l-1.1 1.1M120.7 236.6v.1"/>
<path d="M124.9 236l10.2 10.2-4.8 4.8-10.2-10.2zM125.8 238.3l.9 .9-.6 .6 .6 .7-2.2 2.1-.5-.6-.7 .6-.9-.9zM126.7 239.2l.6 .6M127.3 239.8l4 4-3.4 3.3-3.9-3.9zM146.6 221.5a11.1 11.1 0 0 0 3.7 5.6M146.7 221.5a11.1 11.1 0 0 1 13.2-13.2l2.3 .4 2.3 .1h76.8l25.3 25.3a10.5 10.5 0 0 1 0 14.9M150.3 227.1l25.1 25.2h83.6a9.9 9.9 0 0 0 7.6-3.3M158.4 235.4l-4.6 4.7 1.4 1.4M158.6 235.6l-4.5 4.5 8.2 8.2 4.5-4.5M159.9 236.8l-4.7 4.7M165.1 234.1l.7 .7M165.5 229l1.6-1.5 3.4 3.3-1.5 1.7z"/>
<path d="M165.6 234.1l.2 .2M165.8 234.3l.3-.2h.4l-.7 .7zM165.9 233.4l-.8 .7h.5l.3-.3M166.1 234.1l-.2-.3v-.4l.6 .7M166.1 225.2l1.1 1.1 .4-.5M166.1 225.2v.1M166.3 229.3l1.1-1.1 .3 .3-.2 .2 .2 .2-.7 .7-.2-.2-.2 .2zM166.5 224.8h.1M166.5 224.8l-.4 .4M166.6 229.6l.2 .2M166.8 229.8l1.1-1.1 1.3 1.3-1.1 1.1zM167.2 226.3h.1"/>
<path d="M167.3 229.4l.5-.1-.2-.2 .3 .3h-.6l.3 .3h-.2zM167.7 229.7l.3-.2 .1 .2-.3 .3h-.2zM167.7 236.6l.6 .7M167.7 223.6l1.1 1.1-1.2 1.2-1.1-1.1zM167.7 229.7l.2-.1 .2 .1-.2 .3-.2-.1zM167.7 223.6h.1M167.7 223.5v.1M167.7 228.5l.2 .2M168 230.1l.2-.1 .1 .1zM168.1 223.2l1.1 1.1-.4 .4M168.1 229.9l.2-.1-.1 .1 .2 .2-.5 .1zM168.1 223.2l-.3 .4"/>
<path d="M168.1 227.8l.4 .4M168.1 227.7v.1M168.1 236.6l.2 .3M168.1 231.1l.2 .3M168.3 230.3a.22 .22 0 0 1 .4-.2 .22 .22 0 0 1 0 .4l-.4 .1zM168.3 236.9l.3-.3h.4l-.7 .7zM168.4 230.3l.3-.1v.2l-.3 .2zM168.4 235.9l-.7 .7h.4l.3-.2M168.4 236.4v-.5l.6 .7M168.4 236.4l.2 .2M168.4 228.1h.1M168.5 228.2l1.1-1.2 1.3 1.3-1.2 1.1z"/>
<path d="M168.8 224.7h.1M168.9 226.9h-.5l-.2 .2v.5M169 225.7l1.6-1.6 3.4 3.4-1.6 1.6zM169.2 224.2v.1M169.2 230l.6 .5-1.1 1.1-.4-.2M169.5 230.3l-.3 .2-.2-.2-.7 .7 .2 .1-.2 .3M169.6 227v.1M169.6 227l-.4-.3-1.1 1.1M169.7 229.4l.5 .3M169.8 229.3v.1M170.1 226.3l.2 .2M170.1 229.7h.1"/>
<path d="M170.8 228.3l.4 .4-1 1M170.9 224.8l.3 .3-.2 .2 .2 .3-.7 .7-.2-.2-.2 .2-.3-.3zM171 233.9l.2 .2M171.1 225.8l.3 .2h-.5l-.1 .2 .3 .1h-.2v-.3h.3zM171.2 226.2a.25 .25 0 0 1 .4 .1 .25 .25 0 0 1-.2 .3l-.3-.1zM171.2 225.1l.2 .2M171.2 226.3l.3-.1 .1 .1-.3 .3-.1-.1zM171.2 228.6v.1M171.4 225.3l1.3 1.4-1.1 1.1-1.3-1.3zM171.5 231.7l3.4 3.4-1.6 1.6-3.4-3.4zM171.6 226.5l.2-.1-.1 .1 .2 .2-.5 .1zM171.6 227.8l.2 .2"/>
<path d="M171.7 226.6l.1 .1h-.3zM171.7 233.7l.5-.1-.2-.2 .3 .3h-.5l-.1 .2 .3 .1-.3-.1zM171.8 232.5l.3 .3-.2 .2 .2 .2-.7 .7-.2-.2-.2 .2-.3-.3zM171.8 226.9l.4-.1a.29 .29 0 0 1-.1 .4 .29 .29 0 0 1-.4 0zM172 226.8h.1l.1 .2-.4 .2zM172 234l.3-.2h.2v.3l-.2 .2-.3-.1zM172.1 234l.2-.2 .2 .1-.2 .3h-.2zM172.1 232.8l2 2-1.1 1.2-.3-.4M172.3 234.5h.1M172.3 233l-1.1 1.1 1.3 1.4M172.4 234.4l.2-.2 .1 .2zM172.5 234.1h.2l.1 .3-.5 .1z"/>
<path d="M172.5 231.9v.1M172.5 235.5l.2 .1M172.7 234.6l.3-.2 .1 .3-.3 .3-.2-.1zM172.7 234.6l.3-.2 .1 .1-.2 .4-.2-.1zM172.7 226.7l.5 .5-1.1 1.1-.3-.3M172.8 232.3h.1M172.9 226.9l-.2 .2-.2-.2-.7 .7 .2 .2-.2 .2M173.6 230.8l.4 .4M173.6 234.3l-1.1 1.2M173.7 230.8l-1.2 1.1 .4 .5M173.8 234.5l-.2 .2-.2-.2-.7 .7 .2 .3-.2 .1M174 231.2l1.2 1.3-1.1 1.1-1.2-1.2"/>
<path d="M174 231.2l-1.1 1.2M174 231.2v.1M174.5 233.9h.1M174.6 220.3h.9M174.6 221.4h.9M174.6 220.3l.3 .3M174.6 220.3v1.1M174.9 220.6v.4l-.3 .4M174.9 220.6h.3M174.9 221h.3M175 228.3l3.4 3.3-1.6 1.7-3.4-3.4zM175.2 230.3l.2-.2 .2 .1-.2 .3h-.2z"/>
<path d="M175.2 232.5h.1M175.2 221v-.4l.3-.3v1.1M175.2 232.5l.4 .4M175.2 221l.3 .4M175.3 230.2l.1-.2 .2 .1v.3l-.3 .2-.2-.1zM175.5 230.6l.5-.1-.4 .4zM175.6 230.6h.3l-.2 .2zM175.6 229.3l-.3 .2 .3 .2-.8 .8-.1-.2-.2 .2M175.6 229.3l-.3-.3-1.1 1.2 .5 .5M175.6 229.3l.2 .2M175.6 232.9l-1.1 1.1-.4-.5M175.6 232.8v.1"/>
<path d="M175.8 229.5l1.3 1.3-1.1 1.2-1.3-1.3zM175.9 230.9l.2-.2 .1 .1-.2 .3h-.2zM175.9 230.8h.4l-.1 .2-.3 .2-.1-.1zM176 231.3h.5v-.2l-.2-.1 .3 .1-.1 .3h-.4l.2 .2zM176 234.8v.1M176 232l.2 .2M176.3 234.5h.1M176.9 231.1l.2 .2 .2-.2 .3 .3-1.1 1.1-.3-.3 .2-.2-.2-.2zM176.9 238.5h3.7v3.8h-3.7zM177.1 230.8l.2 .3M177.4 235.5v.1M177.5 235.6l-.5 .4"/>
<path d="M177.5 233.3l1.2 1.1-1.2 1.2-1.1-1.2M177.6 233.2v.1M177.9 232.9h.1M178.2 233a.48 .48 0 0 1 .7 0 .48 .48 0 0 1 0 .7M178.2 220.3l.3 .3v.4M178.2 220.3v1.1l.3-.4M178.2 220.3h.9M178.2 221.4h.9M178.5 220.6h.3M178.5 221h.3M178.6 234.3h.1M178.7 234.3v.1"/>
<path d="M178.8 221v-.4l.3-.3v1.1M178.8 221l.3 .4M179.1 233.9l-.4 .4M179.1 233.9l-1.1-1.1-2.1 2.1 1.1 1.1M179.2 238.5a.46 .46 0 0 1 0-.7 .46 .46 0 0 1 .7 0 .46 .46 0 0 1-.1 .7M181.1 223.1l6.2 6.2M181.4 223.3l-1.2 1.2 2.4 2.4M182.4 238.5h3.7v3.8h-3.7zM183.5 227.8l2.4 2.5 1.2-1.2M183.8 225.7l-1.3 1.3 .9 .9 1.3-1.2M184 220.3l6.2 6.1M184 220.5l-2.6 2.6 5.9 6"/>
<path d="M184 220.5v-.2l-2.9 2.8h.3M184 220.5l6 5.9M184.7 221l1.3-1.3 .9 .9-1.3 1.3M186.4 233.5h.9M186.8 220.7l3 2.9M187.3 229.1l2.7-2.7h.2l-2.9 2.9zM187.9 238.5h3.7v3.8h-3.7zM188.6 224.8l1.2-1.2 1 .9-1.3 1.2M190.7 224.5l.5 .5-1.2 1.2M193 235.5h4.8v2.2h-4.8zM193.5 225.1v.7M193.7 235.8v-7.9h3.7v8.1h-.4"/>
<path d="M194.1 235.8h-.4v1.6h3.3v-1.6h-.4v.3h-.3v1h.3v.3M194.1 235.8v.3h.3v1h-.3v.3M194.1 235.8h.3M194.3 225.2v.6M194.4 230.4h2.3v3.1h-2.3zM194.4 233.9h.5v-.4h1.4v.4h.4v.5h-2.3zM194.4 230h.5v.4h1.4v-.4h.4M194.4 233.5v.4M194.4 237.4v-1.6h1.9v1.6M194.6 236.4l.2-.1 .1 .1-.1 .5h-.2zM194.6 236.4l.3 .1-.1 .4-.2-.1zM195.1 230.7l.3-.2h.4l.3 .1v.3l-.3 .2h-.4l-.3-.1z"/>
<path d="M195.1 232.2l.4-.2h.4l.2 .4-.2 .3h-.6l-.2-.2zM195.2 231.4l.3-.1 .6 .4-.4-.2-.2 .4h-.3l-.1-.2zM195.2 230.7l.6-.2 .2 .2v.2l-.7 .1zM195.2 232.8h.2a.27 .27 0 0 0-.3 .3 .27 .27 0 0 0 .4 .2l.1-.3 .4 .3-.1-.5 .2 .2-.1 .4-.3-.1-.4 .2-.2-.2zM195.2 232.2l.2-.1a.4 .4 0 0 1 .4 0 .4 .4 0 0 1 .2 .4l-.7 .1zM195.3 236.3v.6l-.1-.4-.1 .2h.1M195.3 236.3l-.3 .5h.2M195.3 236.3h.1M195.5 236.4l.2 .1v.4l-.2-.2zM195.5 236.3l.3 .1-.1 .5-.3-.1zM195.9 236.4l.1-.1 .2 .1v.2l-.2 .3h.3h-.4l.3-.3-.1-.2zM195.9 236.5h.1"/>
<path d="M196.3 235.8h.3M196.7 230v-.5h-2.3v.9M196.7 230v.4M196.7 233.5v.4M198.2 237.2v.1M198.5 237.6h.1M199.5 232.4v1v-.5h-.5M199.7 236.5l1.2 1.2-1.1 1.1-1.2-1.1zM199.7 236.6l-.4-.5-1.1 1.1 .4 .5M199.8 238.8l.4 .4M200.2 239.2h.1M200.9 237.7h.1"/>
<path d="M200.9 237.7l.4 .5M201.3 238.2l-1.1 1M201.3 238.2h.1M201.3 238.1v.1M203.1 239.3h.7M203.1 236h.7M203.1 238.6h.7M203.1 236.7h.7M207.9 239.5v.5h-.9M210.1 239.3v.9M228.5 236.5v.8M229.2 236.6v.5"/>
<path d="M231.7 222.1l3.5-3.4 1.5 1.6-3.4 3.4zM232.8 221.5l.2 .2 .2-.2 .7 .8-.2 .1 .2 .2M233 221.3l1.4-1.3 1.1 1.1-1.4 1.3zM233 221.3l-.5 .5 1.1 1.1 .5-.5M233.6 221.5h.3l.2 .4h-.4zM233.6 238v.8M233.6 221.5h.2l.2 .3-.2 .1zM234 221.1l.4 .3v.1l-.1-.1-.2 .2zM234.1 221.2l.1 .2-.1 .1zM234.2 220.9l.2-.1 .3 .4-.3 .1-.3-.3zM234.2 220.9l.4 .1v.2h-.3zM234.5 220.5l.3 .1 .1 .4 .2-.2-.3 .3v-.5h-.2l-.1 .2z"/>
<path d="M235.7 220.9l-.2 .2M236.3 233.6v1M236.3 233.7h.5M238.4 220.6l.4-.5 1.4 1.3-.5 .5-.4-.4 .1-.4-.4-.2-.2 .1zM239.5 228.6v.7M240.2 228.6v.6M240.5 221.3l-.6 .6-.1-.1M240.5 221.2v.1M243.2 235.2h2.6v2.3h-2.6zM243.2 235.2v-1.1h2.6v1.1M243.2 237.5v1.2h2.6v-1.2M243.2 238.6l.1 .1"/>
<path d="M243.2 235.1l.1 .1M243.3 237.5l-.1 .1M243.3 234.1l-.1 .1M243.4 222.6h.3M243.4 222.6l.7 .7M244.1 223.1v.2M244.1 221.9l.1 .2M244.1 221.9l.7 .6M244.1 221.9l-.7 .7M244.2 222.1l.4 .4-.5 .6M244.2 222.1l-.5 .5 .4 .5M244.6 222.5h.2"/>
<path d="M244.8 222.5l-.7 .8M245.7 237.5l.1 .1M245.7 234.1l.1 .1M245.8 238.6l-.1 .1M245.8 235.1l-.1 .1M246 225.1l.2 .1M246.6 225.6v.2M246.7 224.5v.2M246.7 224.5l.7 .6M246.7 224.5l-.7 .6M246.7 224.7l.4 .4-.5 .5M246.7 224.7l-.5 .5 .4 .4"/>
<path d="M247.1 225.1h.3M247.4 225.1l-.8 .7-.6-.7M248.5 227.7h.3M249.1 228.1l.1 .2M249.2 227l.1 .2M249.2 227l.7 .6M249.2 227l-.7 .7M249.3 227.2l.3 .4-.5 .5M249.3 227.2l-.5 .5 .3 .4M249.6 227.6h.3M249.9 227.6l-.7 .7-.7-.6M251 230.2l.3 .1"/>
<path d="M251 230.2l.7 .7M251.7 230.6v.3M251.8 229.5v.2M251.8 229.5l.6 .7M251.8 229.5l-.8 .7M251.8 229.7l.4 .4-.5 .5M251.8 229.7l-.5 .6 .4 .3M252.2 230.1l.2 .1M252.4 230.2l-.7 .7M262.4 222.8l-3.5 3.5M69.7 256.8a1.01 1.01 0 0 0 1.3 .3M71 257.1a19.1 19.1 0 0 0-23.8 12.3 19.1 19.1 0 0 0 11.7 24.1"/>
<path d="M71 257.1a19.1 19.1 0 0 1 13.5 17.9 19.1 19.1 0 0 1-12.7 18.5M109.7 250.9l4.8-4.8 10.2 10.2-4.8 4.9zM112.9 252.7l.6 .6M114.7 242.6h.2M115.4 248.5l.9 .8-.6 .7 .6 .6-2.1 2.1-.7-.6-.6 .6-.9-.9zM115.9 241.4v.2M115.9 251.2l.1-.1 .8 .8-1.5 .2-.1 .4 .2 .2h.6l-.3 .2h-.3l-.4-.3 .1-.5 .3-.3h1.1zM116 241.5l-.1 .1M116.3 252.9l.5-.3a.37 .37 0 0 1 .6 .1l-.1 .4-.7 .6h-.3l-.1-.2zM116.3 249.3l.6 .7M116.3 252.6l.8-.3 .4 .2 .1 .4-.6 .8-.6 .2-.4-.4v-.3zM116.9 250l4 3.9-3.4 3.4-4-4z"/>
<path d="M117.2 254.2l.5-.5 .4 .3zM117.5 253.4l.1-.1 .2 .1 .2-.3 .2 .1-.3 .3 .5 .6-1.6 .3 .8-.9zM117.5 247.1l1 1.1M117.5 257.3l.6 .6M117.5 247v.1M118.2 254.6l.3-.3 .6-.1 .3 .2v.4l-.6 .8-.6 .1-.3-.3v-.3zM118.2 254.8l.4-.4 .4-.1 .3 .3v.2a1.04 1.04 0 0 1-1.1 .7l-.2-.4zM118.5 248.2l.1 .1M118.5 248.2h.2M119.8 244.6a1.45 1.45 0 0 0-1.9 .2 1.45 1.45 0 0 0-.1 1.9M120.7 243.8h.2M120.9 253.9l.6 .7"/>
<path d="M121.5 254.6l-.6 .5-.6-.5-2.2 2.1 .6 .6-.6 .6M121.5 254.6l.9 .8-3.4 3.4-.9-.9M121.9 244.8v.2M122 244.9l3.6 3.7-3.3 3.3-3.7-3.6zM122 244.9l-1.2-1.2-3.4 3.4h.1M122.3 251.9l.1 .1M122.4 252l1 1M122.4 251.8v.2M123.3 242.6l.7 .6M123.4 253h.2M125.6 248.7h.1M125.6 248.6l1.3 1.2-.2 .1"/>
<path d="M126.3 241.1l.1-.1 .9 .8-1.5 .1a.33 .33 0 0 0-.2 .6l.2 .1 .4-.1 .2 .1-.6 .2-.4-.3v-.5l.3-.2 1.2-.1zM126.6 242.7a1.12 1.12 0 0 1 1.1-.5l.2 .2a1.24 1.24 0 0 1-.9 1.4h-.2a.6 .6 0 0 1-.5-.5 .6 .6 0 0 1 .3-.6zM126.7 242.9l.3-.4a.43 .43 0 0 1 .7-.1 .43 .43 0 0 1-.1 .7l-.4 .4a.4 .4 0 0 1-.7-.2zM126.7 249.9l-3.2 3.3-.1-.2M126.7 249.7v.2M127.6 244.1l.5-.6 .4 .4zM127.6 259l10.2 10.2-4.7 4.8-10.3-10.2zM127.9 243.3l.1-.1 .1 .1 .3-.3 .1 .1-.2 .3 .6 .6-1.7 .3 .8-.9zM127.9 247.1l.6 .7M128.5 244.7l.5-.4 .5-.1a.38 .38 0 0 1 .1 .6l-.6 .6h-.3l-.3-.2zM128.6 244.4l.5-.3h.5a.7 .7 0 0 1 .1 .9l-.7 .6-.6-.1-.1-.6zM130.6 259.5v.3l1.1 1.1"/>
<path d="M130.6 259.5v.2M131.3 243.8l1.5 1.5-3.4 3.4-.9-.9M131.9 244.4l-.6 .6-.7-.6-2.1 2.1 .6 .6-.6 .7M133.8 256.4h.2M135 257.4l-1.1-1.1-3.3 3.2M135 257.4l.1 .1M135 257.4v.2M137.1 255.8l3.3-3.4 4 4-3.3 3.4zM138 248.6l10.3 10.2-4.9 4.8-10.2-10.2zM138.8 254.4l.5-.4h.4l.3 .2 .1 .4-.6 .8-.6 .1-.4-.3v-.4zM138.9 254.6l.5-.5h.3l.2 .3-.1 .4-.6 .6h-.3l-.2-.3zM139.5 255.6l1.6-.3-.8 .9 .2 .1-.2 .1-.1-.1-.3 .3-.1-.1 .3-.3z"/>
<path d="M139.8 255.7l.9-.2-.5 .6zM139.8 251.8l-.6 .6 .6 .6-2.1 2.2-.6-.6-.6 .6M139.8 251.8l-.9-.9-3.3 3.4 1.5 1.5M139.8 251.8l.6 .6M140.6 256.4l.6-.5h.4l.3 .3v.5l-.2 .2a.74 .74 0 0 1-1.3 .1zM140.6 256.6l.6-.6h.4l.2 .5-.5 .6a.48 .48 0 0 1-.8-.1zM141.1 259.8l.5 .6M141.1 257.8l1.5-.2 .1-.4-.2-.2-.4 .1-.1-.1 .1-.2h.6l.2 .3v.4l-.2 .3-1.2 .1 .5 .6-.1 .1zM143.8 257l.6 .6 .6-.6 .9 .9-3.3 3.4-1-.9 .6-.6-.6-.7zM144.4 256.4l.6 .6M155.2 241.5l5.8 5.8M165.7 242.6l-4.7 4.7"/>
<path d="M167 244l-4.7 4.7-1.3-1.4M176.9 244.6h3.7v3.7h-3.7zM182.4 244.6h3.7v3.7h-3.7zM187.9 244.6h3.7v3.7h-3.7zM199.4 245l-.1 .5M199.9 243.2h1.6v1.7h-1.6zM199.9 243.2v-.5h1.6v.5M199.9 244.9v.6h1.6v-.6M199.9 245.4v.1M199.9 243.2h.1M199.9 244.9v.1M199.9 242.7h.1"/>
<path d="M200.4 242.6v.1a.45 .45 0 0 1 .7 0M201.1 242.5v.2M201.4 244.9l.1 .1M201.4 242.7h.1M201.5 245.4l-.1 .1M201.5 243.2h-.1M231.1 245.6v.2M231.8 245.4v.6M239.2 241.6h2.6v2.3h-2.6zM239.2 244.9l.1 .1M239.2 241.5l.1 .1M239.2 241.6v-1.1h2.6v1.1"/>
<path d="M239.2 243.9v1.1h2.6v-1.1M239.3 243.9l-.1 .1M239.3 240.5h-.1M239.7 245l.4 .3 .4-.3M241.7 243.9l.1 .1M241.7 240.5h.1M241.8 244.9l-.1 .1M241.8 241.5l-.1 .1M50.7 265.9h7.5v7.5h-7.5zM50.7 278h7.5v7.4h-7.5zM55.3 265.9a.97 .97 0 0 1-.1-1.4 .97 .97 0 0 1 1.4 0 .97 .97 0 0 1 0 1.4M61.7 265.9h7.4v7.5h-7.4z"/>
<path d="M61.7 278h7.4v7.4h-7.4zM72.6 278h7.5v7.4h-7.5zM72.6 265.9h7.5v7.5h-7.5zM108.5 266.2l2 1.9M108.5 266.2h1.4M109.9 266.2l.6 .6M110.7 265.3l-.8 .9M110.7 265.3l.6 .7M110.7 264v1.3M110.7 264l1.9 2M110.7 264l-2.2 2.2M112.6 266h-1.3l-.8 .8v1.3"/>
<path d="M112.6 266l-2.1 2.1M116.1 273.8l2 1.9M117.5 273.8l.6 .6M118.1 274.4l.8-.8h1.3l-2.1 2.1zM118.3 273l-.8 .8h-1.4M118.3 271.7v1.3l.6 .6M118.3 271.7l-2.2 2.1M118.3 271.7l1.9 1.9M126.1 265.6l.6 .6M128.5 261.3l.9 .9-.6 .6 .6 .6-2.1 2.2-.6-.6-.6 .6-1-.9zM129.2 264l.8 .8-1.6 .1v.5l.2 .2 .4-.1 .1 .1-.6 .2-.4-.4 .1-.4 .4-.3h1l-.6-.6zM129.4 265.6l.5-.4h.6l.2 .3-.2 .7a.76 .76 0 0 1-.7 .5 .76 .76 0 0 1-.7-.3l.1-.5z"/>
<path d="M129.4 265.8l.4-.4a.48 .48 0 0 1 .7 .2v.2l-.4 .5a.48 .48 0 0 1-.8 0zM129.4 262.2l.6 .6M130 262.8l4 4-3.4 3.3-3.9-3.9zM130.6 266.2l.3 .1 .2-.3 .2 .1-.3 .3 .6 .6-1.7 .3 .9-.9zM130.6 270.1l.6 .7M130.9 266.5l.3 .4-.9 .1zM131.2 267.5l.5-.4 .5-.1 .3 .3v.4l-.6 .8-.5 .1-.4-.4zM131.4 267.5l.5-.3h.3l.2 .2v.3l-.5 .6-.5 .1-.3-.2zM131.7 260.7h.1M131.7 260.9l3.4-3.4 3.7 3.7-3.4 3.3zM134 266.8l1.5 1.5-3.3 3.4-1-.9M134.6 267.4l-.6 .6-.6-.6-2.2 2.1 .7 .6-.7 .7"/>
<path d="M135.4 264.5l1.1 1.1h.2M135.5 264.4v.2M136.6 265.6h.1M138.7 261.3h.2M138.8 261.2l.1 .1M138.9 261.3l1 1M139.9 262.5l-3.2 3.1M139.9 262.3l.1 .1-.1 .1M139.9 262.3v.2M141.1 268.3v.2M142.1 267.3h.1M142.1 267.3l-1.2 1.1 3.3 3.3"/>
<path d="M142.2 267.2l-.1 .1M144.2 271.7h.2M145.4 270.5v.1M145.5 270.6l-1.1 1.1M145.8 263.5l3.3 3.4-3.6 3.7-3.3-3.4zM145.9 263.4v.2M146.9 262.4l-1.1 1.1M146.9 262.4l.1-.1 .1 .1M146.9 262.4h.2M147.1 262.4l3.3 3.2-1.1 1.2M147.7 262.9a1.5 1.5 0 0 1 2.1 0 1.5 1.5 0 0 1 0 2.1M149.1 266.8h.1"/>
<path d="M149.3 266.8l-.2 .1M150.2 265.6v.1M58.9 293.5h12.9"/>
<circle cx="61.8" cy="148.5" r=".43"/>
<circle cx="66.5" cy="157.5" r=".46"/>
<circle cx="72.3" cy="153.5" r=".46"/>
<circle cx="76" cy="155.7" r=".43"/>
<circle cx="77.6" cy="146.7" r=".43"/>
<circle cx="79.8" cy="158.9" r=".43"/>
<circle cx="80" cy="156.4" r=".46"/>
<circle cx="81.2" cy="151.2" r=".43"/>
<circle cx="81.2" cy="147.4" r=".46"/>
<circle cx="83.6" cy="157.6" r=".46"/>
<circle cx="85.8" cy="159.3" r=".46"/>
<circle cx="91.7" cy="158.7" r=".23"/>
<circle cx="93.8" cy="154.5" r=".43"/>
<circle cx="95.5" cy="158" r=".46"/>
<circle cx="100.7" cy="152.1" r=".43"/>
<circle cx="101.1" cy="147.4" r=".46"/>
<circle cx="108.7" cy="152.5" r=".46"/>
<circle cx="110.7" cy="156.3" r=".43"/>
<circle cx="115.1" cy="159.6" r=".43"/>
<circle cx="115.3" cy="146.8" r=".46"/>
<circle cx="132" cy="159.1" r=".46"/>
<circle cx="145.4" cy="152.4" r="4"/>
<circle cx="43.5" cy="175" r="4"/>
<circle cx="55.3" cy="174.5" r=".46"/>
<circle cx="70.6" cy="162.1" r=".17"/>
<circle cx="70.8" cy="164.4" r=".32"/>
<circle cx="71.8" cy="179.1" r=".26"/>
<circle cx="76.9" cy="169.3" r=".46"/>
<circle cx="77.7" cy="178.1" r=".43"/>
<circle cx="88.7" cy="160.6" r=".46"/>
<circle cx="92.2" cy="160.9" r=".46"/>
<circle cx="92.4" cy="163.6" r=".46"/>
<circle cx="93.2" cy="179.1" r=".46"/>
<circle cx="93.4" cy="166.2" r=".43"/>
<circle cx="93.4" cy="169.7" r=".46"/>
<circle cx="94.3" cy="176.4" r=".46"/>
<circle cx="96.9" cy="176.8" r=".46"/>
<circle cx="101.2" cy="164.1" r=".43"/>
<circle cx="107" cy="178.3" r=".43"/>
<circle cx="114.1" cy="170" r=".46"/>
<circle cx="121.7" cy="176.4" r=".46"/>
<circle cx="123" cy="171.7" r=".46"/>
<circle cx="124" cy="166.9" r=".46"/>
<circle cx="129" cy="176.6" r=".43"/>
<circle cx="133.9" cy="160.8" r=".46"/>
<circle cx="142" cy="164.1" r=".43"/>
<circle cx="206.8" cy="170.2" r=".84"/>
<circle cx="210.9" cy="162.7" r=".98"/>
<circle cx="211" cy="175.6" r=".98"/>
<circle cx="226.9" cy="161.9" r=".84"/>
<circle cx="237.4" cy="173.8" r=".98"/>
<circle cx="240.8" cy="166.6" r=".84"/>
<circle cx="53.6" cy="180" r=".43"/>
<circle cx="65.4" cy="195.7" r="1.22"/>
<circle cx="79.2" cy="180.7" r=".2"/>
<circle cx="88.8" cy="181.1" r=".43"/>
<circle cx="113.8" cy="180.7" r=".46"/>
<circle cx="67.3" cy="217.8" r="1.06"/>
<circle cx="157.1" cy="218.9" r="4"/>
<circle cx="176.3" cy="216.4" r=".23"/>
<circle cx="182.5" cy="218.6" r=".43"/>
<circle cx="193.8" cy="219" r=".46"/>
<circle cx="201.8" cy="218.7" r=".43"/>
<circle cx="221.3" cy="217.7" r=".43"/>
<circle cx="221.3" cy="213.9" r=".46"/>
<circle cx="240.7" cy="215.1" r=".43"/>
<circle cx="160.5" cy="230.6" r=".43"/>
<circle cx="165.8" cy="234" r=".67"/>
<circle cx="168.4" cy="236.6" r=".67"/>
<circle cx="175.1" cy="220.8" r=".67"/>
<circle cx="178.7" cy="220.8" r=".67"/>
<circle cx="186.8" cy="233.7" r=".46"/>
<circle cx="188.5" cy="236.5" r=".46"/>
<circle cx="191.8" cy="222.8" r=".43"/>
<circle cx="193.9" cy="225.5" r=".46"/>
<circle cx="195.4" cy="231.6" r=".21"/>
<circle cx="199.5" cy="232.9" r=".46"/>
<circle cx="201.3" cy="230.6" r=".43"/>
<circle cx="203.5" cy="239" r=".46"/>
<circle cx="203.5" cy="236.3" r=".46"/>
<circle cx="207" cy="224.6" r=".46"/>
<circle cx="207.5" cy="239.8" r=".46"/>
<circle cx="208.7" cy="221" r=".43"/>
<circle cx="209.1" cy="236.2" r=".46"/>
<circle cx="209.1" cy="232.7" r=".43"/>
<circle cx="210.2" cy="230.1" r=".46"/>
<circle cx="210.3" cy="239.7" r=".46"/>
<circle cx="210.3" cy="227.5" r=".46"/>
<circle cx="213.9" cy="227.1" r=".46"/>
<circle cx="215.6" cy="239.4" r=".43"/>
<circle cx="215.6" cy="234.9" r=".43"/>
<circle cx="216.8" cy="225.8" r=".46"/>
<circle cx="218.9" cy="224.1" r=".46"/>
<circle cx="220.1" cy="234.9" r=".43"/>
<circle cx="220.2" cy="239.4" r=".43"/>
<circle cx="222.6" cy="222.9" r=".46"/>
<circle cx="222.7" cy="225.5" r=".43"/>
<circle cx="225.6" cy="235.9" r=".46"/>
<circle cx="226.5" cy="222.2" r=".43"/>
<circle cx="228.7" cy="236.9" r=".46"/>
<circle cx="230.2" cy="220" r=".46"/>
<circle cx="231" cy="225.3" r=".43"/>
<circle cx="233.9" cy="238.4" r=".46"/>
<circle cx="236.1" cy="224" r=".46"/>
<circle cx="236.4" cy="234.1" r=".46"/>
<circle cx="239.8" cy="228.9" r=".46"/>
<circle cx="244.1" cy="222.6" r=".67"/>
<circle cx="246.6" cy="225.1" r=".67"/>
<circle cx="249.2" cy="227.7" r=".67"/>
<circle cx="251.7" cy="230.2" r=".67"/>
<circle cx="129.6" cy="254.5" r="25.1"/>
<circle cx="173.5" cy="243.1" r=".43"/>
<circle cx="180.8" cy="243" r=".46"/>
<circle cx="195.5" cy="244.8" r=".43"/>
<circle cx="199" cy="245.2" r=".43"/>
<circle cx="205.6" cy="243.3" r=".46"/>
<circle cx="208.2" cy="243" r=".46"/>
<circle cx="209.3" cy="245.6" r=".46"/>
<circle cx="210.8" cy="243.5" r=".46"/>
<circle cx="213.5" cy="243.3" r=".46"/>
<circle cx="213.7" cy="247.7" r=".43"/>
<circle cx="224.8" cy="244.6" r=".43"/>
<circle cx="231.5" cy="245.7" r=".43"/>
<circle cx="247.3" cy="241" r=".46"/>
<circle cx="248.9" cy="246.6" r=".43"/>
<circle cx="259" cy="241.6" r="4"/>
<circle cx="58.5" cy="274.8" r=".98"/>
<circle cx="73.8" cy="261.8" r=".98"/>
<circle cx="110.6" cy="266" r="2.12"/>
<circle cx="118.2" cy="273.6" r="2.12"/>
</g>
<g fill="#000">
<circle cx="105.6" cy="164.7" r=".25"/>
<circle cx="107" cy="164.7" r=".25"/>
<circle cx="108.5" cy="164.7" r=".25"/>
<circle cx="109.9" cy="164.7" r=".25"/>
<circle cx="111.6" cy="168.7" r=".25"/>
<circle cx="111.6" cy="167.3" r=".25"/>
<circle cx="111.6" cy="170.1" r=".25"/>
<circle cx="111.6" cy="171.6" r=".25"/>
</g>
<g fill="none" stroke="#000" stroke-width=".25">
<path d="M10.3 110.5h279.9v198.8h-279.9zM42.6 107v3.5M78.5 107v3.5M114.4 107v3.5M150.2 107v7.1M186.1 107v3.5M222 107v3.5M257.9 107v3.5M27.4 130.6h21.6l18.4 26.6M87.7 136.2h13.3l3.5 19.2M152 135h-30l-4.3 10.9M6.7 141.3h3.6"/>
<path d="M69.3 148.1h6.5l.2 6.7M80.9 152h10.4l.4 3.1M290.2 141.3h3.6M6.7 175.6h3.6M59.6 163.4l-24.5 11h-18.7M96.3 175.9l-7.3 26.9h21.1M103.3 179.7l1.2 11.4h22M113.3 175l2.8 3.8h8M121.1 170.3l17.5 19.5h18.5M290.2 175.6h3.6M54.6 180.9l-9.9 12.5h-14.8M101.6 182.6l-.5 14.1h11.2"/>
<path d="M109.7 181.2l.6 2.8h11.2M216.3 196.6l-3.8 4.3M6.7 209.9h7.2M165.7 205.8h13l4.9 12.7M165.8 213.9h9.4l2.3 1.7M286.6 209.9h7.2M287.1 202.3h-54.5l2.4 9.6M135.8 228h2.5l.7 19.1M146.7 228h-8.4l-7.2 10.8M159.5 227.5l4.5 1M208.4 225.5h-6.7l-3.9 2.6M213.8 232.5h-10.5l-4.2 2.8"/>
<path d="M234.7 225.8l3.5 5.6h6.4M6.7 244.3h3.6M114.1 258.5l-6.7 20h-2.5M187.2 252.4l1 3.3M202.3 247.9l1 2.6h11.2M202.6 240.4l3 3.4h10M244.5 240.8l10.2 18h12.9M290.2 244.3h3.6M6.7 278.6h3.6M122.8 267.3l-15.4 11.2h-9.7M152.7 266l7.5 1.3h15.9M290.2 278.6h3.6"/>
<path d="M42.6 309.3v3.6M78.5 309.3v3.6M114.4 309.3v3.6M150.2 305.7v7.2M186.1 309.3v3.6M222 309.3v3.6M257.9 309.3v3.6"/>
<circle cx="76.3" cy="175.1" r="9.1"/>
<circle cx="201.6" cy="213.5" r="16.6"/>
<circle cx="172.2" cy="230.3" r="8.4"/>
<circle cx="184.2" cy="243.3" r="9.5"/>
</g>
<path d="M161 275.6h129.2v33.7h-129.2zM178.2 275.6v7.2M202.6 275.6v33.7M246.4 275.6v33.7M161 282.8h129.2M202.6 289.9h87.6M246.4 302.1h43.8M253.6 302.1v7.2M279.4 302.1v7.2" fill="none" stroke="#000" stroke-width=".34"/>
<g fill="#000" stroke="#000" stroke-width=".2">
<path d="M203.5 279.1h.9l.4 .3h-1v.9l.9 .1-.2 .2h-.7v1h-.3z" fill-rule="evenodd"/>
<path d="M204.2 279.4h.6l.1 .6-.2 .4-.9-.1h.5l.3-.1v-.5l-.2-.3z" fill-rule="evenodd"/>
<path d="M205 279.8h.2l.4 1.5-.2 .3z" fill-rule="evenodd"/>
<path d="M205.9 279.8h.2l-.5 2.2-.4 .1 .2-.2z" fill-rule="evenodd"/>
<path d="M206.3 279.8h.2v.3h.2l-.2 .4v1.1h-.2z" fill-rule="evenodd"/>
<path d="M206.6 279.9l.3-.1v.4l-.4-.1z" fill-rule="evenodd"/>
<path d="M207.3 279.9l.4-.1 .4 .4 .1 .9-.5 .6h-.3l-.2-.3h.5l.2-.2v-1l-.3-.2h-.4z" fill-rule="evenodd"/>
<path d="M208.4 279.1h.2v.9h.3l-.3 .4v.7l.2 .3h-.2v.2h-.2z" fill-rule="evenodd"/>
<path d="M208.6 280l.3-.2 .3 .1a1.57 1.57 0 0 1 .2 1.5l-.4 .3-.4-.2 .4-.1a.93 .93 0 0 0 0-1.4z" fill-rule="evenodd"/>
<path d="M209.9 279.9l.5-.1 .3 .2 .1 1.6-.5-.2 .2-.2v-.4l-.7-.1 .2-.1a.35 .35 0 0 0 .4-.1 .35 .35 0 0 0 0-.4l-.6-.1z" fill-rule="evenodd"/>
<path d="M212.3 280h.4z" fill-rule="evenodd"/>
<path d="M212.1 279.8h.2v.3h.3l-.3 .3v.7l.3 .3-.3 .1v.9h-.2z" fill-rule="evenodd"/>
<path d="M212.5 279.8a.57 .57 0 0 1 .7 .6v.7l-.2 .4-.4 .2-.3-.2a.78 .78 0 0 0 .7-.6 .78 .78 0 0 0-.2-.8l-.5-.1z" fill-rule="evenodd"/>
<path d="M213.7 279.8h.4l.3 .2h-.5l-.2 .2-.1 .8 .3 .4h-.3l-.2-.3v-.6z" fill-rule="evenodd"/>
<path d="M214.7 279.9l.6-.1 .3 .5h-.3l-.2-.3h-.4z" fill-rule="evenodd"/>
<path d="M216.5 279.1h.9l.4 .3h-1.1v.9l1 .1-.2 .2h-.8v1h-.2z" fill-rule="evenodd"/>
<path d="M217.2 279.4h.6v.6l-.1 .4-1-.1h.6l.3-.1v-.5l-.2-.3z" fill-rule="evenodd"/>
<path d="M218 279.8h.2l.4 1.5-.2 .3z" fill-rule="evenodd"/>
<path d="M218.9 279.8h.2l-.5 2.2-.4 .1 .2-.2z" fill-rule="evenodd"/>
<path d="M219.3 279.8h.2v.3h.2l-.2 .4v1.1h-.2z" fill-rule="evenodd"/>
<path d="M219.6 279.9l.3-.1v.4l-.4-.1z" fill-rule="evenodd"/>
<path d="M220.3 279.9l.4-.1 .4 .4v.9l-.4 .6h-.3l-.2-.3h.5l.2-.2v-1l-.3-.2h-.4z" fill-rule="evenodd"/>
<path d="M221.4 279.1h.2v.9h.3l-.3 .4v.7l.2 .3h-.2v.2h-.2z" fill-rule="evenodd"/>
<path d="M221.8 279.8l.4 .1a1.57 1.57 0 0 1 .2 1.5l-.4 .3-.4-.2 .4-.1a.93 .93 0 0 0 0-1.4h-.4z" fill-rule="evenodd"/>
<path d="M222.9 279.9l.5-.1 .3 .2 .1 1.6-.5-.2 .2-.2v-.4l-.7-.1 .2-.1a.41 .41 0 0 0 .5-.4l-.2-.2h-.5z" fill-rule="evenodd"/>
<path d="M225.3 280h.4z" fill-rule="evenodd"/>
<path d="M225.1 279.8h.2v.3h.3l-.3 .3v.7l.3 .3-.3 .1v.9h-.2z" fill-rule="evenodd"/>
<path d="M225.3 280l.2-.2a.57 .57 0 0 1 .7 .6v.7l-.2 .4-.4 .2-.3-.2a.78 .78 0 0 0 .7-.6 .78 .78 0 0 0-.2-.8z" fill-rule="evenodd"/>
<path d="M226.5 280l.4-.2 .5 .2h-.5l-.2 .3-.1 .7 .3 .4h-.3l-.2-.3z" fill-rule="evenodd"/>
<path d="M227.7 279.9l.6-.1 .3 .5h-.3l-.2-.3h-.4z" fill-rule="evenodd"/>
<path d="M203.6 293.8l1.2 .1 .3 .4h-1.2v1.3h1.2l-.4 .4h-.8v1.4h-.3z" fill-rule="evenodd"/>
<path d="M205.1 282.1h.4l-.3 .3z" fill-rule="evenodd"/>
<path d="M204.6 294.3h.6l.1 .8-.2 .5h-1.2l.7-.1a.69 .69 0 0 0 .4-.6 .69 .69 0 0 0-.4-.6z" fill-rule="evenodd"/>
<path d="M205.6 294.9h.3v2.5h-.3z" fill-rule="evenodd"/>
<path d="M205.6 293.8h.3v.5h-.3z" fill-rule="evenodd"/>
<path d="M206.4 295.1h.5a.61 .61 0 0 0-.4 .8h1.1v.3h-1.1l.1 .7 .3 .2h-.5l-.1-.2-.1-1.2z" fill-rule="evenodd"/>
<path d="M206.5 294.9l.4-.1 .3 .1 .4 .5v.5h-1.1h.9l-.2-.6-.2-.2h-.6z" fill-rule="evenodd"/>
<path d="M207.1 280.1h.4a.99 .99 0 0 0-.2 1.1l.3 .2h-.4l-.1-.2z" fill-rule="evenodd"/>
<path d="M206.4 297.1h.7l.2-.5 .3 .2a.68 .68 0 0 1-.9 .6z" fill-rule="evenodd"/>
<path d="M208.6 281.4h.4z" fill-rule="evenodd"/>
<path d="M208.9 295.2l.3-.1-1 2-.3 .3v-.3z" fill-rule="evenodd"/>
<path d="M207.9 294.9h1.3v.2l-1.3 .1z" fill-rule="evenodd"/>
<path d="M207.9 297.4l.3-.3h1.1v.3z" fill-rule="evenodd"/>
<path d="M209.6 295.1h.5a1.33 1.33 0 0 0-.3 1.8l.3 .2h-.5l-.1-.2-.1-1.2z" fill-rule="evenodd"/>
<path d="M209.8 280.1l.4-.1-.2 .2-.1 .2-.2-.1z" fill-rule="evenodd"/>
<path d="M209.8 280.8h.7h-.1a.36 .36 0 0 0-.4 .2 .36 .36 0 0 0 .1 .4l.4 .1-.3 .2-.3-.1-.2-.3z" fill-rule="evenodd"/>
<path d="M209.6 295.1a.69 .69 0 0 1 .8-.3 .69 .69 0 0 1 .5 .7l-.1 1.3a.63 .63 0 0 1-.4 .6 .63 .63 0 0 1-.8-.3h.8l.2-.5-.1-1.2-.3-.3z" fill-rule="evenodd"/>
<path d="M210.1 281.4h.5z" fill-rule="evenodd"/>
<path d="M211.1 279.1h.2v2.5h-.2z" fill-rule="evenodd"/>
<path d="M211.2 296.3l.2-.1 .2 .6 .5 .3h-.8z" fill-rule="evenodd"/>
<path d="M211.6 279.1h.2v2.5h-.2z" fill-rule="evenodd"/>
<path d="M211.5 294l.2-.2h.5l.5 .4h-.9a.65 .65 0 0 0-.2 .8 .65 .65 0 0 0 .7 .4l.6 .6-.1 1.1-.5 .4-.6-.1-.4-.3h.8a.69 .69 0 0 0 .5-.8 .69 .69 0 0 0-.8-.6l-.3-.1-.3-.5z" fill-rule="evenodd"/>
<path d="M212.2 294.2h.5l.2 .7h-.3z" fill-rule="evenodd"/>
<path d="M213.3 294.2l.3-.3v1h.3v.3h-.3v1.7l.1 .2h-.4v-1.9h-.2v-.3h.2z" fill-rule="evenodd"/>
<path d="M213.3 297.1h.6l-.1 .3a.35 .35 0 0 1-.4 0 .35 .35 0 0 1-.1-.3z" fill-rule="evenodd"/>
<path d="M214.2 295.1h.6a.44 .44 0 0 0-.5 .6l-.2-.1z" fill-rule="evenodd"/>
<path d="M214.2 296.1l.9 .1a.67 .67 0 0 0-.8 .7l.2 .2 .6 .1-.2 .1a.55 .55 0 0 1-.9-.2v-.6z" fill-rule="evenodd"/>
<path d="M213.6 281.4h.4l.2-.4h.3l-.4 .7h-.3z" fill-rule="evenodd"/>
<path d="M214 280h.4l.1 .4h-.3z" fill-rule="evenodd"/>
<path d="M214.6 280.1l.5-.1-.2 .1a.41 .41 0 0 0 .4 .5l.3 .4-.1 .5-.3 .2h-.3l-.2-.3h.5a.37 .37 0 0 0 .1-.4 .37 .37 0 0 0-.4-.2l-.3-.3z" fill-rule="evenodd"/>
<path d="M214.6 297.1h.5z" fill-rule="evenodd"/>
<path d="M214.2 295.1l.2-.2a.62 .62 0 0 1 1 .4l.1 2.1h-.3l-.1-.3h-.3l.3-.3v-.7h-.9l.4-.1a.42 .42 0 0 0 .6-.3 .42 .42 0 0 0-.4-.6z" fill-rule="evenodd"/>
<path d="M214.6 281.1h.2l.2 .3h-.3z" fill-rule="evenodd"/>
<path d="M215.8 294.9h.3v.3h.2l-.2 .6v1.6h-.3z" fill-rule="evenodd"/>
<path d="M216.1 295.1h.4l-.2 .1z" fill-rule="evenodd"/>
<path d="M216.2 295a.52 .52 0 0 1 .6-.2 .52 .52 0 0 1 .3 .6v2h-.3v-2l-.1-.2-.6-.1z" fill-rule="evenodd"/>
<path d="M218.1 282.1h.4l-.3 .3z" fill-rule="evenodd"/>
<path d="M217.7 294.9l.2-.1a.44 .44 0 0 1 .6 .3l-.6 .1-.1 .2-.1 1.2 .4 .5h-.5l-.2-.6v-.8z" fill-rule="evenodd"/>
<path d="M217.6 297.1h1a.42 .42 0 0 1-.7 .3z" fill-rule="evenodd"/>
<path d="M218.5 293.8h.3v3.6h-.2v-.3h-.4a1.48 1.48 0 0 0 0-2h.3z" fill-rule="evenodd"/>
<path d="M219.3 295.1h.5l-.2 .1-.1 .5-.3-.1z" fill-rule="evenodd"/>
<path d="M219.3 296.2l.9-.1-.2 .1a.47 .47 0 0 0-.6 .3 .47 .47 0 0 0 .4 .6l.4 .1a.55 .55 0 0 1-.9 .1l-.2-.4z" fill-rule="evenodd"/>
<path d="M219.4 294.9a.67 .67 0 0 1 .7-.1 .67 .67 0 0 1 .4 .6l.1 2h-.3v-.3h-.4l.3-.4v-.6h-.8l.8-.3v-.4l-.2-.3h-.7z" fill-rule="evenodd"/>
<path d="M219.8 297.1h.5z" fill-rule="evenodd"/>
<path d="M220.1 280.1h.4a.99 .99 0 0 0-.2 1.1l.3 .2h-.4l-.2-.2z" fill-rule="evenodd"/>
<path d="M220.9 293.8h.3v3.6h-.3z" fill-rule="evenodd"/>
<path d="M221.7 295.2l.5-.1-.2 .2-.2 .5v.9l.4 .4h-.5l-.1-.3-.1-.8z" fill-rule="evenodd"/>
<path d="M221.6 281.4h.4z" fill-rule="evenodd"/>
<path d="M221.8 294.9l.5-.1a.74 .74 0 0 1 .6 .6l.1 .7-.1 .9-.3 .4-.5 .1-.4-.4h.6l.3-.2 .1-1.1-.1-.4-.3-.3h-.6z" fill-rule="evenodd"/>
<path d="M222.8 280.1l.4-.1-.2 .2-.1 .2-.2-.1z" fill-rule="evenodd"/>
<path d="M222.8 280.8h.7h-.1a.36 .36 0 0 0-.5 .2 .36 .36 0 0 0 .2 .4l.4 .1-.3 .2-.3-.1-.2-.3z" fill-rule="evenodd"/>
<path d="M223.1 281.4h.5z" fill-rule="evenodd"/>
<path d="M223.3 294.9h.3v.3h.2l-.2 .6v1.6h-.3z" fill-rule="evenodd"/>
<path d="M223.6 295.1h.4l-.2 .1z" fill-rule="evenodd"/>
<path d="M223.6 295a.52 .52 0 0 1 .7-.2 .52 .52 0 0 1 .3 .6v2h-.3v-2l-.3-.3h-.4z" fill-rule="evenodd"/>
<path d="M224.1 279.1h.2v2.5h-.2z" fill-rule="evenodd"/>
<path d="M224.6 279.1h.2v2.5h-.2z" fill-rule="evenodd"/>
<path d="M225.1 295.1h.6l-.4 .3-.1 .5 1.2 .1v.2h-1.2l.1 .7 .4 .2h-.6l-.1-.3-.1-1z" fill-rule="evenodd"/>
<path d="M225.3 294.9a.7 .7 0 0 1 1 .6l.1 .4h-1.2h.9l-.1-.5-.2-.3h-.7z" fill-rule="evenodd"/>
<path d="M225.1 297.1h.7l.3-.5 .3 .1-.3 .6-.2 .2h-.4z" fill-rule="evenodd"/>
<path d="M226.5 298.1h1.8v.4h-1.8z" fill-rule="evenodd"/>
<path d="M226.6 281.4h.4l.2-.4h.3l-.4 .7h-.3z" fill-rule="evenodd"/>
<path d="M227 280h.4l.1 .4h-.3z" fill-rule="evenodd"/>
<path d="M227.6 280.1l.5-.1-.2 .1a.41 .41 0 0 0 .4 .5l.3 .4-.1 .5-.3 .2h-.3l-.2-.3h.5a.37 .37 0 0 0 .1-.4 .37 .37 0 0 0-.4-.2l-.3-.3z" fill-rule="evenodd"/>
<path d="M227.6 281.1h.2l.2 .3h-.3z" fill-rule="evenodd"/>
<path d="M228.4 293.8l1.2 .1 .4 .4h-1.3v1.3h1.3l-.4 .4h-.9v1.4h-.3z" fill-rule="evenodd"/>
<path d="M229.4 294.3h.6l.1 .8-.1 .5h-1.3l.9-.1a.76 .76 0 0 0-.1-1.2z" fill-rule="evenodd"/>
<path d="M230.3 293.8h1.8v.5h-.7v3.1h-.3v-3.1h-.8z" fill-rule="evenodd"/>
<path d="M232.5 294.7l.1-.1h.4l-.5 .5z" fill-rule="evenodd"/>
<path d="M233.1 293.8h.2v3.6h-.3v-2.8h-.4z" fill-rule="evenodd"/>
<path d="M234.2 294.2h.5l-.4 .4-.1 1.6a.96 .96 0 0 0 .5 .9l-.5 .1-.2-.5v-1.8z" fill-rule="evenodd"/>
<path d="M234.3 294h.1a.51 .51 0 0 1 .5-.1 .51 .51 0 0 1 .3 .4l.2 .7-.1 1.7-.3 .7-.5 .1-.3-.3 .5-.1 .3-.3 .1-1.5-.2-.9-.2-.2h-.5z" fill-rule="evenodd"/>
<path d="M235.9 294.2h.5l-.3 .2-.2 .9 .1 1.4 .1 .3 .3 .1-.5 .1-.2-.6v-1.6z" fill-rule="evenodd"/>
<path d="M236 294h.1a.41 .41 0 0 1 .7 0l.3 .9-.1 1.9a.61 .61 0 0 1-.4 .6 .61 .61 0 0 1-.6-.1l-.1-.1 .5-.1 .2-.1 .2-.8-.1-1.6-.3-.4h-.5z" fill-rule="evenodd"/>
<path d="M237.2 298.1h1.8v.4h-1.8z" fill-rule="evenodd"/>
<path d="M239.3 294.7l.1-.1h.4l-.5 .5z" fill-rule="evenodd"/>
<path d="M239.9 293.8h.2v3.6h-.3v-2.8h-.4z" fill-rule="evenodd"/>
<path d="M240.9 296.9h.3v.5h-.3z" fill-rule="evenodd"/>
<path d="M241.8 294.7l.2-.1h.4l-.5 .5z" fill-rule="evenodd"/>
<path d="M242.4 293.8h.2v3.6h-.2v-2.8h-.4z" fill-rule="evenodd"/>
<path d="M243.5 296.9h.3v.5h-.3z" fill-rule="evenodd"/>
<path d="M244.4 294.7l.5-.1-.5 .5z" fill-rule="evenodd"/>
<path d="M245 293.8h.2v3.6h-.3v-2.8h-.3z" fill-rule="evenodd"/>
</g>
<g fill="#000">
<path d="M67 157.5l.7-.5 1.1 2.3zM75.6 154.8h.8l-.3 2.5zM91.3 155.2l.8-.1-.1 2.5zM104.1 155.4l.8-.1v2.5zM117.3 145.8l.8 .3-1.3 2.2zM59.4 163l2.5-.7-2.1 1.4zM96.9 173.5l-.2 2.5-.9-.2zM103.1 177.2l.7 2.4-.9 .1zM119.4 168.5l2 1.6-.7 .5zM54.2 180.6l1.9-1.7-1.2 2.2zM101.7 180.1l.3 2.5-.8-.1zM109.1 178.8l1 2.3-.8 .3z"/>
<path d="M183.1 218.7l.8-.3 .5 2.5zM234.6 212l.9-.2 .2 2.5zM130.8 238.5l.7 .5-1.8 1.8zM195.7 229.5l1.9-1.7 .4 .6zM197 236.7l1.9-1.7 .4 .6zM233.4 223.6l1.7 2-.7 .4zM114.9 256.2l-.4 2.5-.8-.3zM138.6 247.1h.8l-.3 2.5zM201.4 245.5l1.3 2.2-.8 .3zM201 238.5l1.9 1.6-.6 .6zM243.2 238.6l1.7 2-.8 .4zM122.6 266.9l2.2-1.1-1.7 1.8z"/>
<path d="M150.2 265.6h2.6l-.1 .8z"/>
</g>
<use href="#words"/>
</svg>
